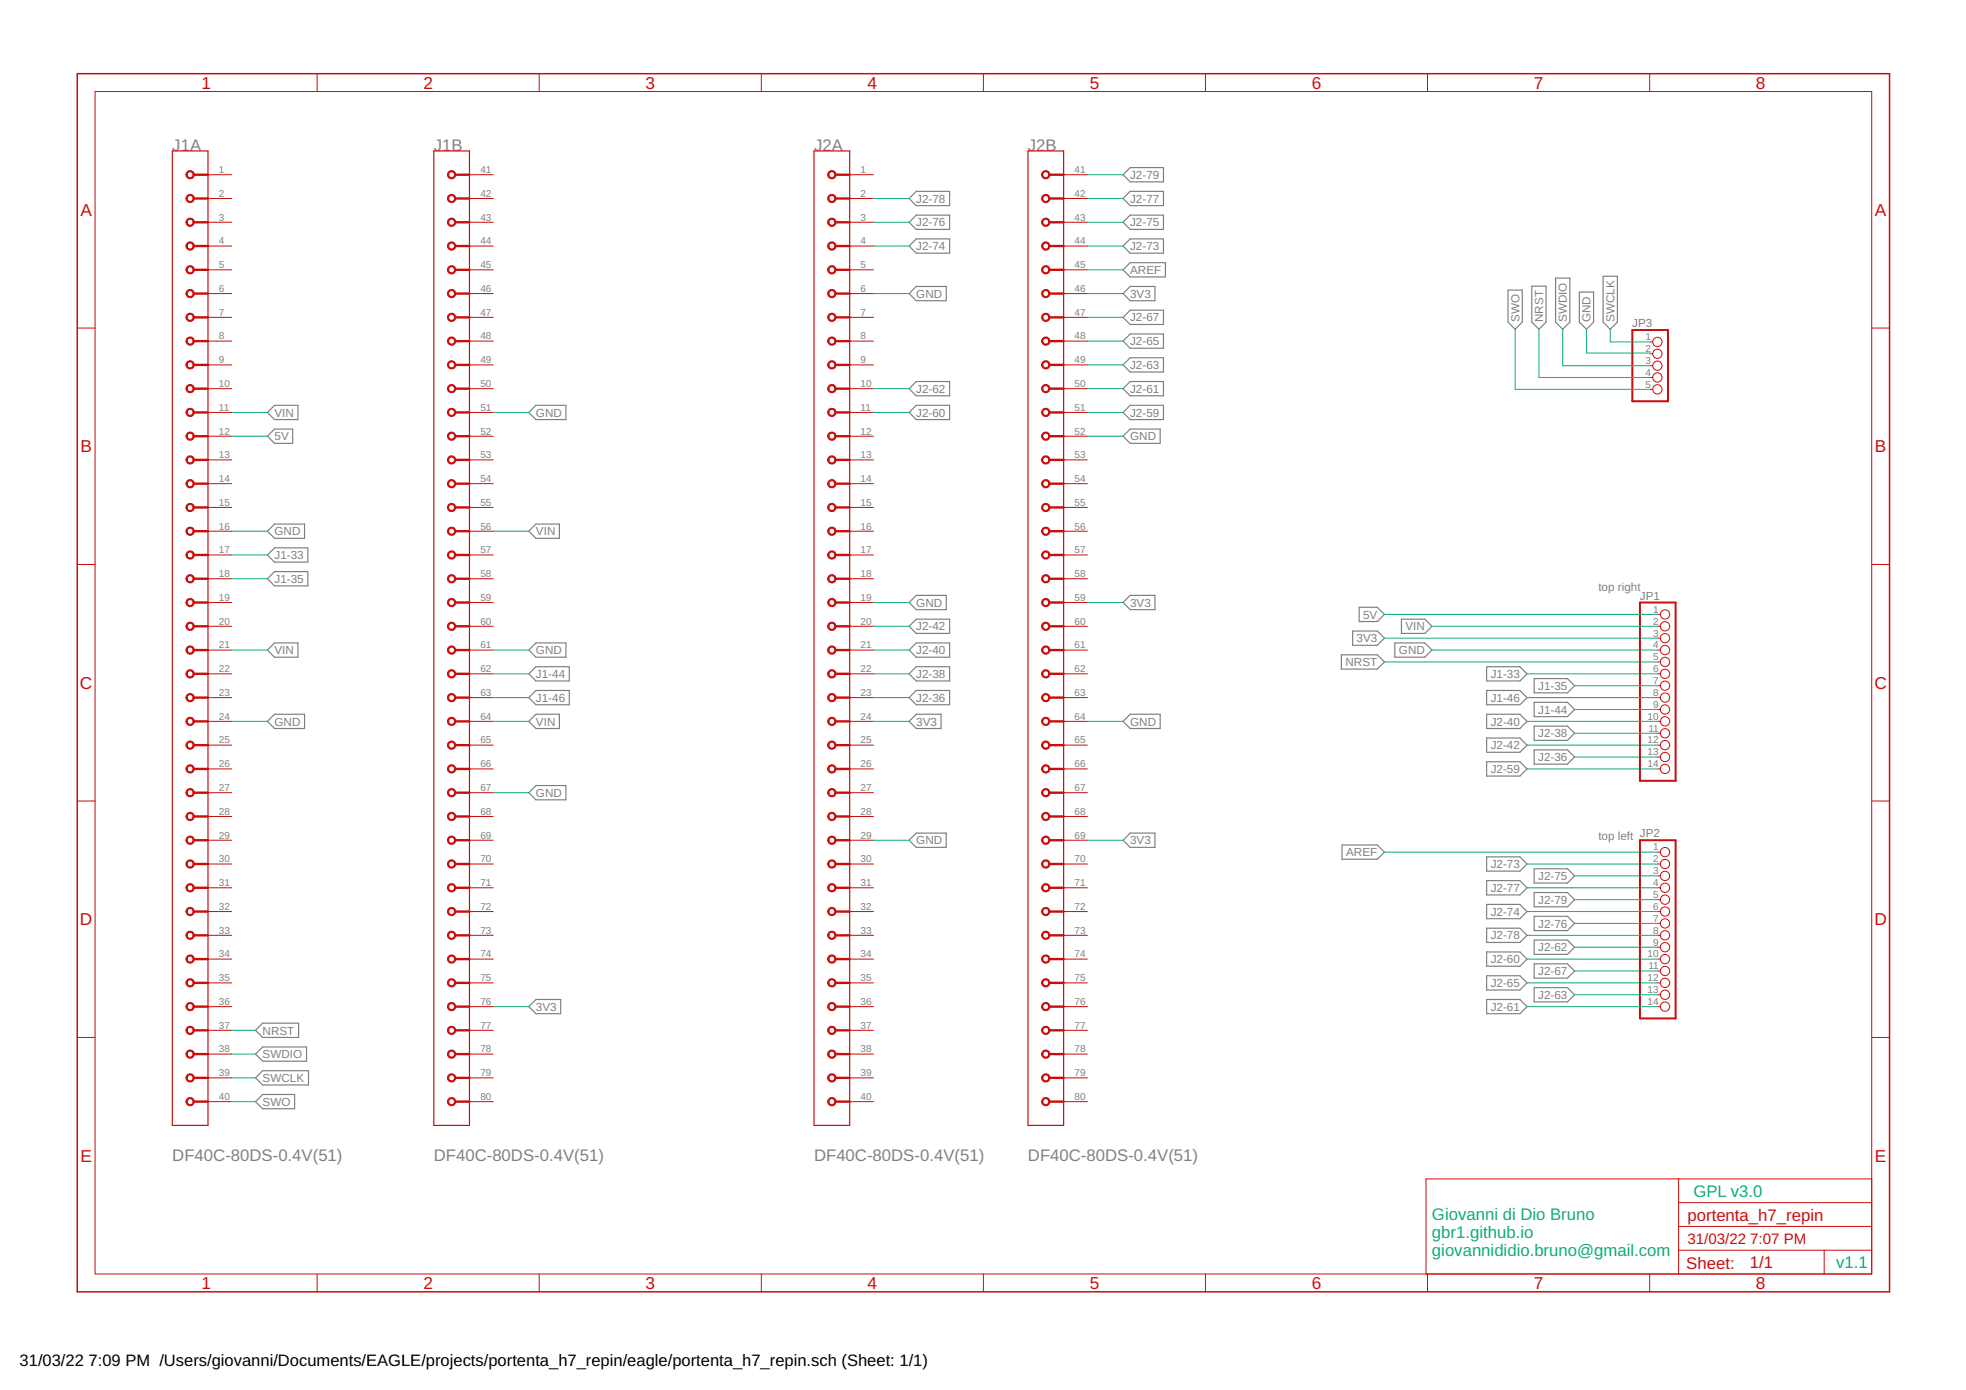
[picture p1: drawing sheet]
<svg xmlns="http://www.w3.org/2000/svg" width="420mm" height="297mm" viewBox="0 0 420 297" stroke-linecap="round" stroke-linejoin="round" font-family="sans-serif">
<defs><g id="words">
<g font-size="3.7" fill="#c90d0c">
<text x="43" y="18.9">1</text>
<text x="90.5" y="18.9">2</text>
<text x="138" y="18.9">3</text>
<text x="185.4" y="18.9">4</text>
<text x="232.9" y="18.9">5</text>
<text x="280.3" y="18.9">6</text>
<text x="327.8" y="18.9">7</text>
<text x="375.3" y="18.9">8</text>
<text x="17.2" y="46.1">A</text>
<text x="400.7" y="46.1">A</text>
<text x="17.2" y="96.7">B</text>
<text x="400.7" y="96.7">B</text>
<text x="17.1" y="147.2">C</text>
<text x="400.6" y="147.2">C</text>
<text x="17.1" y="197.7">D</text>
<text x="400.6" y="197.7">D</text>
<text x="17.2" y="248.3">E</text>
<text x="400.7" y="248.3">E</text>
<text x="43" y="275.4">1</text>
<text x="90.5" y="275.4">2</text>
<text x="138" y="275.4">3</text>
<text x="185.4" y="275.4">4</text>
<text x="232.9" y="275.4">5</text>
<text x="280.3" y="275.4">6</text>
<text x="327.8" y="275.4">7</text>
<text x="375.3" y="275.4">8</text>
</g>
<g font-size="3.6" fill="#808080">
<text x="36.8" y="32.3">J1A</text>
<text x="92.7" y="32.3">J1B</text>
<text x="174" y="32.3">J2A</text>
<text x="219.7" y="32.3">J2B</text>
<text x="36.8" y="248.1">DF40C-80DS-0.4V(51)</text>
<text x="92.7" y="248.1">DF40C-80DS-0.4V(51)</text>
<text x="174" y="248.1">DF40C-80DS-0.4V(51)</text>
<text x="219.7" y="248.1">DF40C-80DS-0.4V(51)</text>
</g>
<g font-size="3.6" fill="#0dab76">
<text x="361.9" y="255.7">GPL v3.0</text>
<text x="306" y="260.8">Giovanni di Dio Bruno</text>
<text x="306" y="264.6">gbr1.github.io</text>
<text x="306" y="268.4">giovannididio.bruno@gmail.com</text>
<text x="392.4" y="271">v1.1</text>
</g>
<g font-size="3.6" fill="#c90d0c">
<text x="360.6" y="260.8">portenta_h7_repin</text>
<text x="360.4" y="271.1">Sheet:</text>
<text x="374" y="271">1/1</text>
</g>
<g font-size="3.5">
<text x="4.2" y="291.8">31/03/22</text>
<text x="18.9" y="291.8">7:09 PM /Users/giovanni/Documents/EAGLE/projects/portenta_h7_repin/eagle/portenta_h7_repin.sch (Sheet: 1/1)</text>
</g>
<g font-size="3.2" fill="#c90d0c">
<text x="360.6" y="265.9">31/03/22</text>
<text x="374.1" y="265.9">7:07 PM</text>
</g>
<g font-size="2.5" fill="#808080">
<text x="241.5" y="38.2">J2-79</text>
<text x="195.8" y="43.3">J2-78</text>
<text x="241.5" y="43.3">J2-77</text>
<text x="195.8" y="53.5">J2-74</text>
<text x="195.8" y="48.4">J2-76</text>
<text x="241.5" y="53.5">J2-73</text>
<text x="241.5" y="48.4">J2-75</text>
<text x="241.5" y="58.5">AREF</text>
<text x="195.8" y="63.6">GND</text>
<text x="241.5" y="63.6">3V3</text>
<text x="241.5" y="68.7">J2-67</text>
<text x="324.7" y="68.8" transform="rotate(-90 324.7 68.8)">SWO</text>
<text x="329.8" y="68.8" transform="rotate(-90 329.8 68.8)">NRST</text>
<text x="334.9" y="68.8" transform="rotate(-90 334.9 68.8)">SWDIO</text>
<text x="339.9" y="68.8" transform="rotate(-90 339.9 68.8)">GND</text>
<text x="345" y="68.8" transform="rotate(-90 345 68.8)">SWCLK</text>
<text x="348.8" y="69.9">JP3</text>
<text x="241.5" y="73.8">J2-65</text>
<text x="195.8" y="83.9">J2-62</text>
<text x="241.5" y="78.9">J2-63</text>
<text x="241.5" y="83.9">J2-61</text>
<text x="58.7" y="89">VIN</text>
<text x="114.5" y="89">GND</text>
<text x="195.8" y="89">J2-60</text>
<text x="241.5" y="89">J2-59</text>
<text x="58.7" y="94.1">5V</text>
<text x="241.5" y="94.1">GND</text>
<text x="58.7" y="114.4">GND</text>
<text x="58.7" y="119.5">J1-33</text>
<text x="114.5" y="114.4">VIN</text>
<text x="58.7" y="124.6">J1-35</text>
<text x="195.8" y="129.7">GND</text>
<text x="241.5" y="129.7">3V3</text>
<text x="341.6" y="126.2">top right</text>
<text x="350.5" y="128.1">JP1</text>
<text x="195.8" y="134.7">J2-42</text>
<text x="289.9" y="137.3">3V3</text>
<text x="291.3" y="132.2">5V</text>
<text x="300.3" y="134.7">VIN</text>
<text x="58.7" y="139.8">VIN</text>
<text x="114.5" y="139.8">GND</text>
<text x="195.8" y="139.8">J2-40</text>
<text x="287.6" y="142.3">NRST</text>
<text x="299" y="139.8">GND</text>
<text x="114.5" y="150">J1-46</text>
<text x="114.5" y="144.9">J1-44</text>
<text x="195.8" y="144.9">J2-38</text>
<text x="195.8" y="150">J2-36</text>
<text x="318.6" y="144.9">J1-33</text>
<text x="318.6" y="150">J1-46</text>
<text x="328.7" y="147.4">J1-35</text>
<text x="58.7" y="155">GND</text>
<text x="114.5" y="155">VIN</text>
<text x="195.8" y="155">3V3</text>
<text x="241.5" y="155">GND</text>
<text x="318.6" y="155">J2-40</text>
<text x="328.7" y="152.5">J1-44</text>
<text x="318.6" y="160.1">J2-42</text>
<text x="328.7" y="157.6">J2-38</text>
<text x="318.6" y="165.2">J2-59</text>
<text x="328.7" y="162.7">J2-36</text>
<text x="114.5" y="170.3">GND</text>
<text x="341.6" y="179.6">top left</text>
<text x="350.5" y="178.9">JP2</text>
<text x="195.8" y="180.4">GND</text>
<text x="241.5" y="180.4">3V3</text>
<text x="287.7" y="183">AREF</text>
<text x="318.6" y="185.5">J2-73</text>
<text x="318.6" y="190.6">J2-77</text>
<text x="328.7" y="188.1">J2-75</text>
<text x="318.6" y="195.7">J2-74</text>
<text x="328.7" y="193.1">J2-79</text>
<text x="318.6" y="200.8">J2-78</text>
<text x="328.7" y="198.2">J2-76</text>
<text x="328.7" y="203.3">J2-62</text>
<text x="318.6" y="205.8">J2-60</text>
<text x="328.7" y="208.4">J2-67</text>
<text x="114.5" y="216">3V3</text>
<text x="318.6" y="210.9">J2-65</text>
<text x="318.6" y="216">J2-61</text>
<text x="328.7" y="213.5">J2-63</text>
<text x="56.1" y="221.1">NRST</text>
<text x="56.1" y="226.2">SWDIO</text>
<text x="56.1" y="231.2">SWCLK</text>
<text x="56.1" y="236.3">SWO</text>
</g>
<g font-size="2.1" fill="#808080">
<text x="46.8" y="37">1</text>
<text x="102.7" y="37">41</text>
<text x="183.9" y="37">1</text>
<text x="229.6" y="37">41</text>
<text x="46.8" y="42.1">2</text>
<text x="46.8" y="47.1">3</text>
<text x="102.7" y="42.1">42</text>
<text x="102.7" y="47.1">43</text>
<text x="183.9" y="42.1">2</text>
<text x="183.9" y="47.1">3</text>
<text x="229.6" y="42.1">42</text>
<text x="229.6" y="47.1">43</text>
<text x="46.8" y="52.2">4</text>
<text x="102.7" y="52.2">44</text>
<text x="183.9" y="52.2">4</text>
<text x="229.6" y="52.2">44</text>
<text x="46.8" y="57.3">5</text>
<text x="102.7" y="57.3">45</text>
<text x="183.9" y="57.3">5</text>
<text x="229.6" y="57.3">45</text>
<text x="46.8" y="62.4">6</text>
<text x="102.7" y="62.4">46</text>
<text x="183.9" y="62.4">6</text>
<text x="229.6" y="62.4">46</text>
<text x="46.8" y="67.5">7</text>
<text x="102.7" y="67.5">47</text>
<text x="183.9" y="67.5">7</text>
<text x="229.6" y="67.5">47</text>
<text x="46.8" y="72.5">8</text>
<text x="46.8" y="77.6">9</text>
<text x="102.7" y="72.5">48</text>
<text x="102.7" y="77.6">49</text>
<text x="183.9" y="72.5">8</text>
<text x="183.9" y="77.6">9</text>
<text x="229.6" y="72.5">48</text>
<text x="229.6" y="77.6">49</text>
<text x="351.7" y="72.7">1</text>
<text x="351.7" y="75.2">2</text>
<text x="351.7" y="77.8">3</text>
<text x="46.8" y="82.7">10</text>
<text x="102.7" y="82.7">50</text>
<text x="183.9" y="82.7">10</text>
<text x="229.6" y="82.7">50</text>
<text x="351.7" y="80.3">4</text>
<text x="351.7" y="82.9">5</text>
<text x="46.8" y="87.8">11</text>
<text x="102.7" y="87.8">51</text>
<text x="183.9" y="87.8">11</text>
<text x="229.6" y="87.8">51</text>
<text x="46.8" y="92.9">12</text>
<text x="102.7" y="92.9">52</text>
<text x="183.9" y="92.9">12</text>
<text x="229.6" y="92.9">52</text>
<text x="46.8" y="97.9">13</text>
<text x="102.7" y="97.9">53</text>
<text x="183.9" y="97.9">13</text>
<text x="229.6" y="97.9">53</text>
<text x="46.8" y="103">14</text>
<text x="102.7" y="103">54</text>
<text x="183.9" y="103">14</text>
<text x="229.6" y="103">54</text>
<text x="46.8" y="108.1">15</text>
<text x="46.8" y="113.2">16</text>
<text x="102.7" y="108.1">55</text>
<text x="102.7" y="113.2">56</text>
<text x="183.9" y="108.1">15</text>
<text x="183.9" y="113.2">16</text>
<text x="229.6" y="108.1">55</text>
<text x="229.6" y="113.2">56</text>
<text x="46.8" y="118.2">17</text>
<text x="102.7" y="118.2">57</text>
<text x="183.9" y="118.2">17</text>
<text x="229.6" y="118.2">57</text>
<text x="46.8" y="123.3">18</text>
<text x="102.7" y="123.3">58</text>
<text x="183.9" y="123.3">18</text>
<text x="229.6" y="123.3">58</text>
<text x="46.8" y="128.4">19</text>
<text x="102.7" y="128.4">59</text>
<text x="183.9" y="128.4">19</text>
<text x="229.6" y="128.4">59</text>
<text x="353.3" y="130.9">1</text>
<text x="46.8" y="133.5">20</text>
<text x="102.7" y="133.5">60</text>
<text x="183.9" y="133.5">20</text>
<text x="229.6" y="133.5">60</text>
<text x="353.3" y="133.5">2</text>
<text x="353.3" y="136">3</text>
<text x="46.8" y="138.6">21</text>
<text x="46.8" y="143.6">22</text>
<text x="102.7" y="138.6">61</text>
<text x="102.7" y="143.6">62</text>
<text x="183.9" y="138.6">21</text>
<text x="183.9" y="143.6">22</text>
<text x="229.6" y="138.6">61</text>
<text x="229.6" y="143.6">62</text>
<text x="353.3" y="138.6">4</text>
<text x="353.3" y="141.1">5</text>
<text x="353.3" y="143.6">6</text>
<text x="46.8" y="148.7">23</text>
<text x="102.7" y="148.7">63</text>
<text x="183.9" y="148.7">23</text>
<text x="229.6" y="148.7">63</text>
<text x="353.3" y="146.2">7</text>
<text x="353.3" y="148.7">8</text>
<text x="46.8" y="153.8">24</text>
<text x="102.7" y="153.8">64</text>
<text x="183.9" y="153.8">24</text>
<text x="229.6" y="153.8">64</text>
<text x="352.1" y="153.8">10</text>
<text x="353.3" y="151.3">9</text>
<text x="46.8" y="158.9">25</text>
<text x="102.7" y="158.9">65</text>
<text x="183.9" y="158.9">25</text>
<text x="229.6" y="158.9">65</text>
<text x="352.1" y="158.9">12</text>
<text x="352.1" y="161.4">13</text>
<text x="352.3" y="156.3">11</text>
<text x="46.8" y="164">26</text>
<text x="102.7" y="164">66</text>
<text x="183.9" y="164">26</text>
<text x="229.6" y="164">66</text>
<text x="352.1" y="164">14</text>
<text x="46.8" y="169">27</text>
<text x="102.7" y="169">67</text>
<text x="183.9" y="169">27</text>
<text x="229.6" y="169">67</text>
<text x="46.8" y="174.1">28</text>
<text x="46.8" y="179.2">29</text>
<text x="102.7" y="174.1">68</text>
<text x="102.7" y="179.2">69</text>
<text x="183.9" y="174.1">28</text>
<text x="183.9" y="179.2">29</text>
<text x="229.6" y="174.1">68</text>
<text x="229.6" y="179.2">69</text>
<text x="46.8" y="184.3">30</text>
<text x="102.7" y="184.3">70</text>
<text x="183.9" y="184.3">30</text>
<text x="229.6" y="184.3">70</text>
<text x="353.3" y="181.7">1</text>
<text x="353.3" y="184.3">2</text>
<text x="46.8" y="189.4">31</text>
<text x="102.7" y="189.4">71</text>
<text x="183.9" y="189.4">31</text>
<text x="229.6" y="189.4">71</text>
<text x="353.3" y="186.8">3</text>
<text x="353.3" y="189.4">4</text>
<text x="353.3" y="191.9">5</text>
<text x="46.8" y="194.4">32</text>
<text x="102.7" y="194.4">72</text>
<text x="183.9" y="194.4">32</text>
<text x="229.6" y="194.4">72</text>
<text x="353.3" y="194.4">6</text>
<text x="353.3" y="197">7</text>
<text x="46.8" y="199.5">33</text>
<text x="102.7" y="199.5">73</text>
<text x="183.9" y="199.5">33</text>
<text x="229.6" y="199.5">73</text>
<text x="353.3" y="199.5">8</text>
<text x="353.3" y="202.1">9</text>
<text x="46.8" y="204.6">34</text>
<text x="46.8" y="209.7">35</text>
<text x="102.7" y="204.6">74</text>
<text x="102.7" y="209.7">75</text>
<text x="183.9" y="204.6">34</text>
<text x="183.9" y="209.7">35</text>
<text x="229.6" y="204.6">74</text>
<text x="229.6" y="209.7">75</text>
<text x="352.1" y="204.6">10</text>
<text x="352.1" y="209.7">12</text>
<text x="352.3" y="207.1">11</text>
<text x="46.8" y="214.8">36</text>
<text x="102.7" y="214.8">76</text>
<text x="183.9" y="214.8">36</text>
<text x="229.6" y="214.8">76</text>
<text x="352.1" y="212.2">13</text>
<text x="352.1" y="214.8">14</text>
<text x="46.8" y="219.8">37</text>
<text x="102.7" y="219.8">77</text>
<text x="183.9" y="219.8">37</text>
<text x="229.6" y="219.8">77</text>
<text x="46.8" y="224.9">38</text>
<text x="102.7" y="224.9">78</text>
<text x="183.9" y="224.9">38</text>
<text x="229.6" y="224.9">78</text>
<text x="46.8" y="230">39</text>
<text x="102.7" y="230">79</text>
<text x="183.9" y="230">39</text>
<text x="229.6" y="230">79</text>
<text x="46.8" y="235.1">40</text>
<text x="102.7" y="235.1">80</text>
<text x="183.9" y="235.1">40</text>
<text x="229.6" y="235.1">80</text>
</g>
</g></defs>
<g fill="none" stroke="#808080" stroke-width=".25">
<path d="M240 37.3l1.5-1.5h7.1v3.1h-7.1zM195.8 51.1h7.1v3h-7.1l-1.5-1.5zM195.8 46h7.1v3h-7.1l-1.5-1.5zM195.8 40.9h7.1v3h-7.1l-1.5-1.5zM240 57.7l1.5-1.6h7.6v3.1h-7.6zM240 52.6l1.5-1.5h7.1v3h-7.1zM240 42.4l1.5-1.5h7.1v3h-7.1zM240 47.5l1.5-1.5h7.1v3h-7.1zM332.4 59.4h3.1v9.4l-1.5 1.6-1.6-1.6zM342.6 59h3.1v9.8l-1.6 1.6-1.5-1.6zM195.8 61.2h6.4v3.1h-6.4l-1.5-1.6zM240 67.8l1.5-1.5h7.1v3h-7.1z"/>
<path d="M240 72.9l1.5-1.5h7.1v3h-7.1zM240 78l1.5-1.5h7.1v3h-7.1zM240 62.7l1.5-1.5h5.3v3.1h-5.3zM322.3 62h3v6.8l-1.5 1.6-1.5-1.6zM327.4 61.2h3v7.6l-1.5 1.6-1.5-1.6zM337.5 62.4h3.1v6.4l-1.6 1.6-1.5-1.6zM57.1 93.2l1.6-1.5h3.8v3h-3.8zM58.7 86.6h5v3.1h-5l-1.6-1.6zM113 88.1l1.5-1.5h6.4v3.1h-6.4zM194.3 88.1l1.5-1.5h7.1v3.1h-7.1zM194.3 83.1l1.5-1.6h7.1v3.1h-7.1zM240 83.1l1.5-1.6h7.1v3.1h-7.1z"/>
<path d="M240 88.1l1.5-1.5h7.1v3.1h-7.1zM241.5 91.7h6.4v3h-6.4l-1.5-1.5zM57.1 118.6l1.6-1.5h7.1v3h-7.1zM58.7 112h6.4v3h-6.4l-1.6-1.5zM113 113.5l1.5-1.5h5v3h-5zM57.1 123.7l1.6-1.5h7.1v3h-7.1zM58.7 137.4h5v3h-5l-1.6-1.5zM114.5 137.4h6.4v3h-6.4l-1.5-1.5zM195.8 132.3h7.1v3.1h-7.1l-1.5-1.6zM195.8 137.4h7.1v3h-7.1l-1.5-1.5zM195.8 127.2h6.4v3.1h-6.4l-1.5-1.5zM240 128.8l1.5-1.6h5.3v3.1h-5.3z"/>
<path d="M286.7 139.9h7.6l1.6 1.6-1.6 1.5h-7.6zM289.1 134.9h5.2l1.6 1.5-1.6 1.5h-5.2zM290.5 129.8h3.8l1.6 1.5-1.6 1.5h-3.8zM298.1 137.4h6.4l1.5 1.5-1.5 1.5h-6.4zM299.5 132.3h5l1.5 1.5-1.5 1.6h-5zM58.7 152.6h6.4v3.1h-6.4l-1.6-1.5zM113 154.2l1.5-1.6h5v3.1h-5zM113 144l1.5-1.5h7.2v3h-7.2zM113 149.1l1.5-1.5h7.2v3h-7.2zM195.8 142.5h7.1v3h-7.1l-1.5-1.5zM195.8 147.6h7.1v3h-7.1l-1.5-1.5zM195.8 152.6h5.3v3.1h-5.3l-1.5-1.5z"/>
<path d="M241.5 152.6h6.4v3.1h-6.4l-1.5-1.5zM317.7 142.5h7.1l1.5 1.5-1.5 1.5h-7.1zM317.7 147.6h7.1l1.5 1.5-1.5 1.5h-7.1zM317.7 152.6h7.1l1.5 1.6-1.5 1.5h-7.1zM317.7 157.7h7.1l1.5 1.5-1.5 1.6h-7.1zM327.9 145h7.1l1.5 1.5-1.5 1.6h-7.1zM327.9 150.1h7.1l1.5 1.5-1.5 1.5h-7.1zM327.9 155.2h7.1l1.5 1.5-1.5 1.5h-7.1zM113 169.4l1.5-1.5h6.4v3h-6.4zM195.8 178h6.4v3.1h-6.4l-1.5-1.5zM240 179.6l1.5-1.6h5.3v3.1h-5.3zM317.7 162.8h7.1l1.5 1.5-1.5 1.5h-7.1z"/>
<path d="M327.9 160.3h7.1l1.5 1.5-1.5 1.5h-7.1zM286.8 180.6h7.5l1.6 1.5-1.6 1.5h-7.5zM317.7 183.1h7.1l1.5 1.5-1.5 1.6h-7.1zM317.7 188.2h7.1l1.5 1.5-1.5 1.5h-7.1zM317.7 193.3h7.1l1.5 1.5-1.5 1.5h-7.1zM317.7 198.4h7.1l1.5 1.5-1.5 1.5h-7.1zM327.9 185.7h7.1l1.5 1.5-1.5 1.5h-7.1zM327.9 190.7h7.1l1.5 1.6-1.5 1.5h-7.1zM327.9 195.8h7.1l1.5 1.5-1.5 1.6h-7.1zM56.1 218.7h7.7v3h-7.7l-1.5-1.5zM113 215.1l1.5-1.5h5.3v3h-5.3zM317.7 203.4h7.1l1.5 1.6-1.5 1.5h-7.1z"/>
<path d="M317.7 208.5h7.1l1.5 1.5-1.5 1.6h-7.1zM317.7 213.6h7.1l1.5 1.5-1.5 1.5h-7.1zM327.9 200.9h7.1l1.5 1.5-1.5 1.5h-7.1zM327.9 206h7.1l1.5 1.5-1.5 1.5h-7.1zM327.9 211.1h7.1l1.5 1.5-1.5 1.5h-7.1zM56.1 228.8h9.8v3.1h-9.8l-1.5-1.6zM56.1 223.7h9.4v3.1h-9.4l-1.5-1.5zM56.1 233.9h6.9v3h-6.9l-1.5-1.5z"/>
</g>
<path d="M36.8 32.3h7.6v208.2h-7.6zM92.7 32.3h7.6v208.2h-7.6zM174 32.3h7.6v208.2h-7.6zM219.7 32.3h7.6v208.2h-7.6z" fill="none" stroke="#c90d0c" stroke-width=".25"/>
<g fill="none" stroke="#c90d0c" stroke-width=".51">
<path d="M41.4 37.3h3M97.3 37.3h3M178.5 37.3h3.1M224.3 37.3h3M41.4 42.4h3M41.4 47.5h3M41.4 52.6h3M41.4 57.7h3M97.3 42.4h3M97.3 47.5h3M97.3 52.6h3M97.3 57.7h3"/>
<path d="M178.5 42.4h3.1M178.5 47.5h3.1M178.5 52.6h3.1M178.5 57.7h3.1M224.3 42.4h3M224.3 47.5h3M224.3 52.6h3M224.3 57.7h3M41.4 62.7h3M41.4 67.8h3M41.4 72.9h3M41.4 78h3"/>
<path d="M97.3 62.7h3M97.3 67.8h3M97.3 72.9h3M97.3 78h3M178.5 62.7h3.1M178.5 67.8h3.1M178.5 72.9h3.1M178.5 78h3.1M224.3 62.7h3M224.3 67.8h3M224.3 72.9h3M224.3 78h3"/>
<path d="M41.4 83.1h3M41.4 88.1h3M41.4 93.2h3M41.4 98.3h3M97.3 83.1h3M97.3 88.1h3M97.3 93.2h3M97.3 98.3h3M178.5 83.1h3.1M178.5 88.1h3.1M178.5 93.2h3.1M178.5 98.3h3.1"/>
<path d="M224.3 83.1h3M224.3 88.1h3M224.3 93.2h3M224.3 98.3h3M41.4 103.4h3M41.4 108.4h3M41.4 113.5h3M41.4 118.6h3M97.3 103.4h3M97.3 108.4h3M97.3 113.5h3M97.3 118.6h3"/>
<path d="M178.5 103.4h3.1M178.5 108.4h3.1M178.5 113.5h3.1M178.5 118.6h3.1M224.3 103.4h3M224.3 108.4h3M224.3 113.5h3M224.3 118.6h3M41.4 123.7h3M41.4 128.8h3M41.4 133.8h3M41.4 138.9h3"/>
<path d="M97.3 123.7h3M97.3 128.8h3M97.3 133.8h3M97.3 138.9h3M178.5 123.7h3.1M178.5 128.8h3.1M178.5 133.8h3.1M178.5 138.9h3.1M224.3 123.7h3M224.3 128.8h3M224.3 133.8h3M224.3 138.9h3"/>
<path d="M41.4 144h3M41.4 149.1h3M41.4 154.2h3M41.4 159.2h3M97.3 144h3M97.3 149.1h3M97.3 154.2h3M97.3 159.2h3M178.5 144h3.1M178.5 149.1h3.1M178.5 154.2h3.1M178.5 159.2h3.1"/>
<path d="M224.3 144h3M224.3 149.1h3M224.3 154.2h3M224.3 159.2h3M41.4 164.3h3M41.4 169.4h3M41.4 174.5h3M41.4 179.6h3M97.3 164.3h3M97.3 169.4h3M97.3 174.5h3M97.3 179.6h3"/>
<path d="M178.5 164.3h3.1M178.5 169.4h3.1M178.5 174.5h3.1M178.5 179.6h3.1M224.3 164.3h3M224.3 169.4h3M224.3 174.5h3M224.3 179.6h3M41.4 184.6h3M41.4 189.7h3M41.4 194.8h3M41.4 199.9h3"/>
<path d="M97.3 184.6h3M97.3 189.7h3M97.3 194.8h3M97.3 199.9h3M178.5 184.6h3.1M178.5 189.7h3.1M178.5 194.8h3.1M178.5 199.9h3.1M224.3 184.6h3M224.3 189.7h3M224.3 194.8h3M224.3 199.9h3"/>
<path d="M41.4 205h3M41.4 210h3M41.4 215.1h3M97.3 205h3M97.3 210h3M97.3 215.1h3M178.5 205h3.1M178.5 210h3.1M178.5 215.1h3.1M224.3 205h3M224.3 210h3M224.3 215.1h3"/>
<path d="M41.4 220.2h3M41.4 225.3h3M41.4 230.3h3M41.4 235.4h3M97.3 220.2h3M97.3 225.3h3M97.3 230.3h3M97.3 235.4h3M178.5 220.2h3.1M178.5 225.3h3.1M178.5 230.3h3.1M178.5 235.4h3.1"/>
<path d="M224.3 220.2h3M224.3 225.3h3M224.3 230.3h3M224.3 235.4h3"/>
</g>
<g fill="none" stroke="#c90d0c" stroke-width=".21">
<path d="M20.3 19.6h379.7v252.6h-379.7zM67.8 15.7v3.9M115.2 15.7v3.9M162.7 15.7v3.9M210.2 15.7v3.9M257.6 15.7v3.9M305.1 15.7v3.9M352.6 15.7v3.9M44.4 37.3l.1 .1M44.4 37.3h5.1M100.3 37.3h5.1M100.3 37.3l.1 .1"/>
<path d="M181.6 37.3h5.1M181.6 37.3v.1M232.4 37.3l-5.1 .1M44.4 42.4h.1M44.4 47.5h.1M44.4 52.6h.1M44.4 42.4h5.1M44.4 47.5h5.1M44.4 52.6h5.1M49.5 57.7h-5M100.3 42.4h5.1M100.3 47.5h5.1"/>
<path d="M100.3 52.6h5.1M100.3 42.4h.1M100.3 47.5h.1M100.3 52.6h.1M105.4 57.7h-5M181.6 42.4h5.1M181.6 47.5h5.1M181.6 52.6h5.1M181.6 42.4h.1M181.6 47.5h.1M181.6 52.6h.1M186.7 57.7h-5.1"/>
<path d="M232.4 42.4h-5.1M232.4 47.5h-5.1M232.4 52.6h-5.1M232.4 57.7h-5.1M16.5 70.1h3.8M49.5 62.7l-5 .1M49.5 67.8h-5M49.5 72.9h-5M49.5 78h-5M105.4 62.7l-5 .1M105.4 67.8h-5M105.4 72.9h-5"/>
<path d="M105.4 78h-5M186.7 62.7l-5.1 .1M186.7 67.8h-5.1M186.7 72.9h-5.1M186.7 78h-5.1M232.4 62.7l-5.1 .1M232.4 67.8h-5.1M232.4 72.9h-5.1M232.4 78h-5.1M352.7 73.1h.5M352.7 75.6h.5M352.7 78.1h.5"/>
<path d="M400 70.1h3.8M44.4 83.1h.1M44.4 88.1l.1 .1M44.4 93.2h.1M44.4 83.1h5.1M44.4 88.1h5.1M44.4 93.2h5.1M49.5 98.3h-5M100.3 83.1h5.1M100.3 88.1h5.1M100.3 93.2h5.1M100.3 83.1h.1"/>
<path d="M100.3 88.1l.1 .1M100.3 93.2h.1M105.4 98.3h-5M181.6 83.1h5.1M181.6 88.1h5.1M181.6 93.2h5.1M181.6 83.1h.1M181.6 88.1v.1M181.6 93.2h.1M186.7 98.3h-5.1M232.4 83.1h-5.1M232.4 88.1l-5.1 .1"/>
<path d="M232.4 93.2h-5.1M232.4 98.3h-5.1M352.7 80.7h.5M352.7 83.2h.5M44.4 103.4h.1M44.4 108.4l.1 .1M44.4 113.5h.1M44.4 118.6h.1M44.4 103.4h5.1M44.4 108.4h5.1M44.4 113.5h5.1M44.4 118.6h5.1"/>
<path d="M100.3 103.4h5.1M100.3 108.4h5.1M100.3 113.5h5.1M100.3 118.6h5.1M100.3 103.4h.1M100.3 108.4l.1 .1M100.3 113.5h.1M100.3 118.6h.1M181.6 103.4h5.1M181.6 108.4h5.1M181.6 113.5h5.1M181.6 118.6h5.1"/>
<path d="M181.6 103.4h.1M181.6 108.4v.1M181.6 113.5h.1M181.6 118.6h.1M232.4 103.4h-5.1M232.4 108.4l-5.1 .1M232.4 113.5h-5.1M232.4 118.6h-5.1M16.5 120.6h3.8M44.4 123.7h.1M44.4 128.8h.1M44.4 133.8l.1 .1"/>
<path d="M44.4 138.9h.1M44.4 123.7h5.1M44.4 128.8h5.1M44.4 133.8h5.1M44.4 138.9h5.1M100.3 123.7h5.1M100.3 128.8h5.1M100.3 133.8h5.1M100.3 138.9h5.1M100.3 123.7h.1M100.3 128.8h.1M100.3 133.8l.1 .1"/>
<path d="M100.3 138.9h.1M181.6 123.7h5.1M181.6 128.8h5.1M181.6 133.8h5.1M181.6 138.9h5.1M181.6 123.7h.1M181.6 128.8h.1M181.6 133.8v.1M181.6 138.9h.1M232.4 123.7h-5.1M232.4 128.8h-5.1M232.4 133.8l-5.1 .1"/>
<path d="M232.4 138.9h-5.1M354.3 133.8h.6M354.3 138.9h.6M354.3 131.3h.6M354.3 136.4h.6M400 120.6h3.8M49.5 144h-5M49.5 149.1h-5M49.5 154.2h-5M49.5 159.2l-5 .1M105.4 144h-5M105.4 149.1h-5"/>
<path d="M105.4 154.2h-5M105.4 159.2l-5 .1M186.7 144h-5.1M186.7 149.1h-5.1M186.7 154.2h-5.1M186.7 159.2l-5.1 .1M232.4 144h-5.1M232.4 149.1h-5.1M232.4 154.2h-5.1M232.4 159.2l-5.1 .1M354.3 144h.6M354.3 149.1h.6"/>
<path d="M354.3 154.2h.6M354.3 159.2h.6M354.3 141.5h.6M354.3 146.5h.6M354.3 151.6h.6M354.3 156.7h.6M16.5 171.2h3.8M44.4 169.4h.1M44.4 174.5h.1M44.4 179.6h.1M44.4 169.4h5.1M44.4 174.5h5.1"/>
<path d="M44.4 179.6h5.1M49.5 164.3h-5M100.3 169.4h5.1M100.3 174.5h5.1M100.3 179.6h5.1M100.3 169.4h.1M100.3 174.5h.1M100.3 179.6h.1M105.4 164.3h-5M181.6 169.4h5.1M181.6 174.5h5.1M181.6 179.6h5.1"/>
<path d="M181.6 169.4h.1M181.6 174.5h.1M181.6 179.6h.1M186.7 164.3h-5.1M232.4 164.3h-5.1M232.4 169.4h-5.1M232.4 174.5h-5.1M232.4 179.6h-5.1M354.3 164.3h.6M354.3 161.8h.6M400 171.2h3.8M44.4 184.6l.1 .1"/>
<path d="M44.4 189.7h.1M44.4 194.8h.1M44.4 199.9h.1M44.4 184.6h5.1M44.4 189.7h5.1M44.4 194.8h5.1M44.4 199.9h5.1M100.3 184.6h5.1M100.3 189.7h5.1M100.3 194.8h5.1M100.3 199.9h5.1M100.3 184.6l.1 .1"/>
<path d="M100.3 189.7h.1M100.3 194.8h.1M100.3 199.9h.1M181.6 184.6h5.1M181.6 189.7h5.1M181.6 194.8h5.1M181.6 199.9h5.1M181.6 184.6v.1M181.6 189.7h.1M181.6 194.8h.1M181.6 199.9h.1M232.4 184.6l-5.1 .1"/>
<path d="M232.4 189.7h-5.1M232.4 194.8h-5.1M232.4 199.9h-5.1M354.3 184.6h.6M354.3 189.7h.6M354.3 194.8h.6M354.3 199.9h.6M354.3 182.1h.6M354.3 187.2h.6M354.3 192.3h.6M354.3 197.3h.6M49.5 205h-5"/>
<path d="M49.5 210l-5 .1M49.5 215.1h-5M105.4 205h-5M105.4 210l-5 .1M105.4 215.1h-5M186.7 205h-5.1M186.7 210l-5.1 .1M186.7 215.1h-5.1M232.4 205h-5.1M232.4 210l-5.1 .1M232.4 215.1h-5.1M354.3 205h.6"/>
<path d="M354.3 210h.6M354.3 215.1h.6M354.3 202.4h.6M354.3 207.5h.6M354.3 212.6h.6M16.5 221.7h3.8M44.4 220.2h.1M44.4 225.3h.1M44.4 220.2h5.1M44.4 225.3h5.1M49.5 230.3l-5 .1M49.5 235.4h-5"/>
<path d="M100.3 220.2h5.1M100.3 225.3h5.1M100.3 220.2h.1M100.3 225.3h.1M105.4 230.3l-5 .1M105.4 235.4h-5M181.6 220.2h5.1M181.6 225.3h5.1M181.6 220.2h.1M181.6 225.3h.1M186.7 230.3l-5.1 .1M186.7 235.4h-5.1"/>
<path d="M232.4 220.2h-5.1M232.4 225.3h-5.1M232.4 230.3l-5.1 .1M232.4 235.4h-5.1M400 221.7h3.8M358.7 251.9v20.3M358.7 257h41.3M400 251.9h-95.2v20.3M67.8 272.2v3.9M115.2 272.2v3.9M162.7 272.2v3.9M210.2 272.2v3.9"/>
<path d="M257.6 272.2v3.9M305.1 272.2v3.9M352.6 272.2v3.9M358.7 267.2h41.3M358.7 262.1h41.3M389.8 267.2v5"/>
<circle cx="354.2" cy="73.1" r=".99"/>
<circle cx="354.2" cy="78.1" r=".99"/>
<circle cx="354.2" cy="75.6" r=".99"/>
<circle cx="354.2" cy="80.7" r=".99"/>
<circle cx="354.2" cy="83.2" r=".99"/>
<circle cx="355.8" cy="131.3" r=".99"/>
<circle cx="355.8" cy="133.8" r=".99"/>
<circle cx="355.8" cy="138.9" r=".99"/>
<circle cx="355.8" cy="136.4" r=".99"/>
<circle cx="355.8" cy="144" r=".99"/>
<circle cx="355.8" cy="146.5" r=".99"/>
<circle cx="355.8" cy="141.5" r=".99"/>
<circle cx="355.8" cy="149.1" r=".99"/>
<circle cx="355.8" cy="151.6" r=".99"/>
<circle cx="355.8" cy="159.2" r=".99"/>
<circle cx="355.8" cy="154.2" r=".99"/>
<circle cx="355.8" cy="156.7" r=".99"/>
<circle cx="355.8" cy="161.8" r=".99"/>
<circle cx="355.8" cy="164.3" r=".99"/>
<circle cx="355.8" cy="187.2" r=".99"/>
<circle cx="355.8" cy="182.1" r=".99"/>
<circle cx="355.8" cy="184.6" r=".99"/>
<circle cx="355.8" cy="189.7" r=".99"/>
<circle cx="355.8" cy="194.8" r=".99"/>
<circle cx="355.8" cy="197.3" r=".99"/>
<circle cx="355.8" cy="199.9" r=".99"/>
<circle cx="355.8" cy="192.3" r=".99"/>
<circle cx="355.8" cy="205" r=".99"/>
<circle cx="355.8" cy="212.6" r=".99"/>
<circle cx="355.8" cy="202.4" r=".99"/>
<circle cx="355.8" cy="210" r=".99"/>
<circle cx="355.8" cy="207.5" r=".99"/>
<circle cx="355.8" cy="215.1" r=".99"/>
</g>
<g fill="#c90d0c" stroke="#c90d0c" stroke-width=".21">
<path d="M39.9 36.8a.88 .88 0 0 1 1.5 0 .88 .88 0 0 1-.5 1.4 .88 .88 0 0 1-1.1-.9h.2a.63 .63 0 0 1 .9-.5 .63 .63 0 0 1 .1 1.1 .63 .63 0 0 1-1-.4v-.2h-.2z" fill-rule="evenodd"/>
<path d="M39.9 41.9a.88 .88 0 0 1 1.5 0 .88 .88 0 0 1-.5 1.4 .88 .88 0 0 1-1.1-.9h.2a.63 .63 0 0 1 .9-.5 .63 .63 0 0 1 .1 1.1 .63 .63 0 0 1-1-.4v-.2h-.2z" fill-rule="evenodd"/>
<path d="M39.9 46.9a.88 .88 0 0 1 1.5 .1 .88 .88 0 0 1-.5 1.3 .88 .88 0 0 1-1.1-.8h.2a.63 .63 0 0 1 .9-.5 .63 .63 0 0 1 .1 1 .63 .63 0 0 1-1-.3v-.2h-.2z" fill-rule="evenodd"/>
<path d="M39.9 52a.88 .88 0 0 1 1.5 .1 .88 .88 0 0 1-.5 1.3 .88 .88 0 0 1-1.1-.8h.2a.63 .63 0 0 1 .9-.5 .63 .63 0 0 1 .1 1 .63 .63 0 0 1-1-.3v-.2h-.2z" fill-rule="evenodd"/>
<path d="M39.9 57.1a.88 .88 0 0 1 1.5 .1 .88 .88 0 0 1-.5 1.3 .88 .88 0 0 1-1.1-.8h.2a.63 .63 0 0 1 .9-.6 .63 .63 0 0 1 .1 1.1 .63 .63 0 0 1-1-.3v-.2h-.2z" fill-rule="evenodd"/>
<path d="M39.9 62.2a.88 .88 0 0 1 1.5 0 .88 .88 0 0 1-.5 1.4 .88 .88 0 0 1-1.1-.9h.2a.63 .63 0 0 1 .9-.5 .63 .63 0 0 1 .1 1.1 .63 .63 0 0 1-1-.4v-.2h-.2z" fill-rule="evenodd"/>
<path d="M39.9 67.3a.88 .88 0 0 1 1.5 0 .88 .88 0 0 1-.5 1.4 .88 .88 0 0 1-1.1-.9h.2a.63 .63 0 0 1 .9-.5 .63 .63 0 0 1 .1 1 .63 .63 0 0 1-1-.3v-.2h-.2z" fill-rule="evenodd"/>
<path d="M39.9 72.3a.88 .88 0 0 1 1.5 .1 .88 .88 0 0 1-.5 1.3 .88 .88 0 0 1-1.1-.8h.2a.63 .63 0 0 1 .9-.5 .63 .63 0 0 1 .1 1 .63 .63 0 0 1-1-.3v-.2h-.2z" fill-rule="evenodd"/>
<path d="M39.9 77.4a.88 .88 0 0 1 1.5 .1 .88 .88 0 0 1-.5 1.3 .88 .88 0 0 1-1.1-.8h.2a.63 .63 0 0 1 .9-.6 .63 .63 0 0 1 .1 1.1 .63 .63 0 0 1-1-.3v-.2h-.2z" fill-rule="evenodd"/>
<path d="M39.9 82.5a.88 .88 0 0 1 1.5 .1 .88 .88 0 0 1-.5 1.3 .88 .88 0 0 1-1.1-.8h.2a.63 .63 0 0 1 .9-.6 .63 .63 0 0 1 .1 1.1 .63 .63 0 0 1-1-.4v-.1h-.2z" fill-rule="evenodd"/>
<path d="M39.9 87.6a.88 .88 0 0 1 1.5 0 .88 .88 0 0 1-.5 1.4 .88 .88 0 0 1-1.1-.9h.2a.63 .63 0 0 1 .9-.5 .63 .63 0 0 1 .1 1.1 .63 .63 0 0 1-1-.4v-.2h-.2z" fill-rule="evenodd"/>
<path d="M39.9 92.7a.88 .88 0 0 1 1.5 0 .88 .88 0 0 1-.5 1.4 .88 .88 0 0 1-1.1-.9h.2a.63 .63 0 0 1 .9-.5 .63 .63 0 0 1 .1 1 .63 .63 0 0 1-1-.3v-.2h-.2z" fill-rule="evenodd"/>
<path d="M39.9 97.7a.88 .88 0 0 1 1.5 .1 .88 .88 0 0 1-.5 1.3 .88 .88 0 0 1-1.1-.8h.2a.63 .63 0 0 1 .9-.5 .63 .63 0 0 1 .1 1 .63 .63 0 0 1-1-.3v-.2h-.2z" fill-rule="evenodd"/>
<path d="M39.9 102.8a.88 .88 0 0 1 1.5 .1 .88 .88 0 0 1-.5 1.3 .88 .88 0 0 1-1.1-.8h.2a.63 .63 0 0 1 .9-.6 .63 .63 0 0 1 .1 1.1 .63 .63 0 0 1-1-.3v-.2h-.2z" fill-rule="evenodd"/>
<path d="M39.9 107.9a.88 .88 0 0 1 1.5 .1 .88 .88 0 0 1-.5 1.3 .88 .88 0 0 1-1.1-.9h.2a.63 .63 0 0 1 .9-.5 .63 .63 0 0 1 .1 1.1 .63 .63 0 0 1-1-.4v-.2h-.2z" fill-rule="evenodd"/>
<path d="M39.9 113a.88 .88 0 0 1 1.5 0 .88 .88 0 0 1-.5 1.4 .88 .88 0 0 1-1.1-.9h.2a.63 .63 0 0 1 .9-.5 .63 .63 0 0 1 .1 1.1 .63 .63 0 0 1-1-.4v-.2h-.2z" fill-rule="evenodd"/>
<path d="M39.9 118.1a.88 .88 0 0 1 1.5 0 .88 .88 0 0 1-.5 1.4 .88 .88 0 0 1-1.1-.9h.2a.63 .63 0 0 1 .9-.5 .63 .63 0 0 1 .1 1 .63 .63 0 0 1-1-.3v-.2h-.2z" fill-rule="evenodd"/>
<path d="M39.9 123.1a.88 .88 0 0 1 1.5 .1 .88 .88 0 0 1-.5 1.3 .88 .88 0 0 1-1.1-.8h.2a.63 .63 0 0 1 .9-.5 .63 .63 0 0 1 .1 1 .63 .63 0 0 1-1-.3v-.2h-.2z" fill-rule="evenodd"/>
<path d="M39.9 128.2a.88 .88 0 0 1 1.5 .1 .88 .88 0 0 1-.5 1.3 .88 .88 0 0 1-1.1-.8h.2a.63 .63 0 0 1 .9-.6 .63 .63 0 0 1 .1 1.1 .63 .63 0 0 1-1-.3v-.2h-.2z" fill-rule="evenodd"/>
<path d="M39.9 133.3a.88 .88 0 0 1 1.5 0 .88 .88 0 0 1-.5 1.4 .88 .88 0 0 1-1.1-.9h.2a.63 .63 0 0 1 .9-.5 .63 .63 0 0 1 .1 1.1 .63 .63 0 0 1-1-.4v-.2h-.2z" fill-rule="evenodd"/>
<path d="M39.9 138.4a.88 .88 0 0 1 1.5 0 .88 .88 0 0 1-.5 1.4 .88 .88 0 0 1-1.1-.9h.2a.63 .63 0 0 1 .9-.5 .63 .63 0 0 1 .1 1.1 .63 .63 0 0 1-1-.4v-.2h-.2z" fill-rule="evenodd"/>
<path d="M39.9 143.4a.88 .88 0 0 1 1.5 .1 .88 .88 0 0 1-.5 1.3 .88 .88 0 0 1-1.1-.8h.2a.63 .63 0 0 1 .9-.5 .63 .63 0 0 1 .1 1 .63 .63 0 0 1-1-.3v-.2h-.2z" fill-rule="evenodd"/>
<path d="M39.9 148.5a.88 .88 0 0 1 1.5 .1 .88 .88 0 0 1-.5 1.3 .88 .88 0 0 1-1.1-.8h.2a.63 .63 0 0 1 .9-.5 .63 .63 0 0 1 .1 1 .63 .63 0 0 1-1-.3v-.2h-.2z" fill-rule="evenodd"/>
<path d="M39.9 153.6a.88 .88 0 0 1 1.5 .1 .88 .88 0 0 1-.5 1.3 .88 .88 0 0 1-1.1-.8h.2a.63 .63 0 0 1 .9-.6 .63 .63 0 0 1 .1 1.1 .63 .63 0 0 1-1-.3v-.2h-.2z" fill-rule="evenodd"/>
<path d="M39.9 158.7a.88 .88 0 0 1 1.5 0 .88 .88 0 0 1-.5 1.4 .88 .88 0 0 1-1.1-.9h.2a.63 .63 0 0 1 .9-.5 .63 .63 0 0 1 .1 1.1 .63 .63 0 0 1-1-.4v-.2h-.2z" fill-rule="evenodd"/>
<path d="M39.9 163.8a.88 .88 0 0 1 1.5 0 .88 .88 0 0 1-.5 1.4 .88 .88 0 0 1-1.1-.9h.2a.63 .63 0 0 1 .9-.5 .63 .63 0 0 1 .1 1.1 .63 .63 0 0 1-1-.4v-.2h-.2z" fill-rule="evenodd"/>
<path d="M39.9 168.8a.88 .88 0 0 1 1.5 .1 .88 .88 0 0 1-.5 1.3 .88 .88 0 0 1-1.1-.8h.2a.63 .63 0 0 1 .9-.5 .63 .63 0 0 1 .1 1 .63 .63 0 0 1-1-.3v-.2h-.2z" fill-rule="evenodd"/>
<path d="M39.9 173.9a.88 .88 0 0 1 1.5 .1 .88 .88 0 0 1-.5 1.3 .88 .88 0 0 1-1.1-.8h.2a.63 .63 0 0 1 .9-.5 .63 .63 0 0 1 .1 1 .63 .63 0 0 1-1-.3v-.2h-.2z" fill-rule="evenodd"/>
<path d="M39.9 179a.88 .88 0 0 1 1.5 .1 .88 .88 0 0 1-.5 1.3 .88 .88 0 0 1-1.1-.8h.2a.63 .63 0 0 1 .9-.6 .63 .63 0 0 1 .1 1.1 .63 .63 0 0 1-1-.3v-.2h-.2z" fill-rule="evenodd"/>
<path d="M39.9 184.1a.88 .88 0 0 1 1.5 0 .88 .88 0 0 1-.5 1.4 .88 .88 0 0 1-1.1-.9h.2a.63 .63 0 0 1 .9-.5 .63 .63 0 0 1 .1 1.1 .63 .63 0 0 1-1-.4v-.2h-.2z" fill-rule="evenodd"/>
<path d="M39.9 189.2a.88 .88 0 0 1 1.5 0 .88 .88 0 0 1-.5 1.4 .88 .88 0 0 1-1.1-.9h.2a.63 .63 0 0 1 .9-.5 .63 .63 0 0 1 .1 1 .63 .63 0 0 1-1-.3v-.2h-.2z" fill-rule="evenodd"/>
<path d="M39.9 194.2a.88 .88 0 0 1 1.5 .1 .88 .88 0 0 1-.5 1.3 .88 .88 0 0 1-1.1-.8h.2a.63 .63 0 0 1 .9-.5 .63 .63 0 0 1 .1 1 .63 .63 0 0 1-1-.3v-.2h-.2z" fill-rule="evenodd"/>
<path d="M39.9 199.3a.88 .88 0 0 1 1.5 .1 .88 .88 0 0 1-.5 1.3 .88 .88 0 0 1-1.1-.8h.2a.63 .63 0 0 1 .9-.6 .63 .63 0 0 1 .1 1.1 .63 .63 0 0 1-1-.3v-.2h-.2z" fill-rule="evenodd"/>
<path d="M39.9 204.4a.88 .88 0 0 1 1.5 .1 .88 .88 0 0 1-.5 1.3 .88 .88 0 0 1-1.1-.8h.2a.63 .63 0 0 1 .9-.6 .63 .63 0 0 1 .1 1.1 .63 .63 0 0 1-1-.4v-.1h-.2z" fill-rule="evenodd"/>
<path d="M39.9 209.5a.88 .88 0 0 1 1.5 0 .88 .88 0 0 1-.5 1.4 .88 .88 0 0 1-1.1-.9h.2a.63 .63 0 0 1 .9-.5 .63 .63 0 0 1 .1 1.1 .63 .63 0 0 1-1-.4v-.2h-.2z" fill-rule="evenodd"/>
<path d="M39.9 214.6a.88 .88 0 0 1 1.5 0 .88 .88 0 0 1-.5 1.4 .88 .88 0 0 1-1.1-.9h.2a.63 .63 0 0 1 .9-.5 .63 .63 0 0 1 .1 1 .63 .63 0 0 1-1-.3v-.2h-.2z" fill-rule="evenodd"/>
<path d="M39.9 219.6a.88 .88 0 0 1 1.5 .1 .88 .88 0 0 1-.5 1.3 .88 .88 0 0 1-1.1-.8h.2a.63 .63 0 0 1 .9-.5 .63 .63 0 0 1 .1 1 .63 .63 0 0 1-1-.3v-.2h-.2z" fill-rule="evenodd"/>
<path d="M39.9 224.7a.88 .88 0 0 1 1.5 .1 .88 .88 0 0 1-.5 1.3 .88 .88 0 0 1-1.1-.8h.2a.63 .63 0 0 1 .9-.6 .63 .63 0 0 1 .1 1.1 .63 .63 0 0 1-1-.3v-.2h-.2z" fill-rule="evenodd"/>
<path d="M39.9 229.8a.88 .88 0 0 1 1.5 .1 .88 .88 0 0 1-.5 1.3 .88 .88 0 0 1-1.1-.9h.2a.63 .63 0 0 1 .9-.5 .63 .63 0 0 1 .1 1.1 .63 .63 0 0 1-1-.4v-.2h-.2z" fill-rule="evenodd"/>
<path d="M39.9 234.9a.88 .88 0 0 1 1.5 0 .88 .88 0 0 1-.5 1.4 .88 .88 0 0 1-1.1-.9h.2a.63 .63 0 0 1 .9-.5 .63 .63 0 0 1 .1 1.1 .63 .63 0 0 1-1-.4v-.2h-.2z" fill-rule="evenodd"/>
<path d="M95.8 36.8a.89 .89 0 0 1 1.4 0 .89 .89 0 0 1-.4 1.3 .89 .89 0 0 1-1.2-.8h.3a.63 .63 0 0 1 .9-.5 .63 .63 0 0 1 .1 1.1 .63 .63 0 0 1-1-.4v-.2h-.3z" fill-rule="evenodd"/>
<path d="M95.8 41.9a.89 .89 0 0 1 1.4 0 .89 .89 0 0 1-.4 1.3 .89 .89 0 0 1-1.2-.8h.3a.63 .63 0 0 1 .9-.5 .63 .63 0 0 1 .1 1.1 .63 .63 0 0 1-1-.4v-.2h-.3z" fill-rule="evenodd"/>
<path d="M95.8 46.9a.89 .89 0 0 1 1.4 0 .89 .89 0 0 1-.4 1.4 .89 .89 0 0 1-1.2-.8h.3a.63 .63 0 0 1 .9-.5 .63 .63 0 0 1 .1 1 .63 .63 0 0 1-1-.3v-.2h-.3z" fill-rule="evenodd"/>
<path d="M95.8 52a.89 .89 0 0 1 1.4 0 .89 .89 0 0 1-.4 1.4 .89 .89 0 0 1-1.2-.8h.3a.63 .63 0 0 1 .9-.5 .63 .63 0 0 1 .1 1 .63 .63 0 0 1-1-.3v-.2h-.3z" fill-rule="evenodd"/>
<path d="M95.8 57.1a.89 .89 0 0 1 1.4 0 .89 .89 0 0 1-.4 1.4 .89 .89 0 0 1-1.2-.8h.3a.63 .63 0 0 1 .9-.6 .63 .63 0 0 1 .1 1.1 .63 .63 0 0 1-1-.3v-.2h-.3z" fill-rule="evenodd"/>
<path d="M95.8 62.2a.89 .89 0 0 1 1.4 0 .89 .89 0 0 1-.4 1.3 .89 .89 0 0 1-1.2-.8h.3a.63 .63 0 0 1 .9-.5 .63 .63 0 0 1 .1 1.1 .63 .63 0 0 1-1-.4v-.2h-.3z" fill-rule="evenodd"/>
<path d="M95.8 67.3a.89 .89 0 0 1 1.4 0 .89 .89 0 0 1-.4 1.3 .89 .89 0 0 1-1.2-.8h.3a.63 .63 0 0 1 .9-.5 .63 .63 0 0 1 .1 1 .63 .63 0 0 1-1-.3v-.2h-.3z" fill-rule="evenodd"/>
<path d="M95.8 72.3a.89 .89 0 0 1 1.4 0 .89 .89 0 0 1-.4 1.4 .89 .89 0 0 1-1.2-.8h.3a.63 .63 0 0 1 .9-.5 .63 .63 0 0 1 .1 1 .63 .63 0 0 1-1-.3v-.2h-.3z" fill-rule="evenodd"/>
<path d="M95.8 77.4a.89 .89 0 0 1 1.4 0 .89 .89 0 0 1-.4 1.4 .89 .89 0 0 1-1.2-.8h.3a.63 .63 0 0 1 .9-.6 .63 .63 0 0 1 .1 1.1 .63 .63 0 0 1-1-.3v-.2h-.3z" fill-rule="evenodd"/>
<path d="M95.8 82.5a.89 .89 0 0 1 1.4 0 .89 .89 0 0 1-.4 1.4 .89 .89 0 0 1-1.2-.8h.3a.63 .63 0 0 1 .9-.6 .63 .63 0 0 1 .1 1.1 .63 .63 0 0 1-1-.4v-.1h-.3z" fill-rule="evenodd"/>
<path d="M95.8 87.6a.89 .89 0 0 1 1.4 0 .89 .89 0 0 1-.4 1.3 .89 .89 0 0 1-1.2-.8h.3a.63 .63 0 0 1 .9-.5 .63 .63 0 0 1 .1 1.1 .63 .63 0 0 1-1-.4v-.2h-.3z" fill-rule="evenodd"/>
<path d="M95.8 92.7a.89 .89 0 0 1 1.4 0 .89 .89 0 0 1-.4 1.3 .89 .89 0 0 1-1.2-.8h.3a.63 .63 0 0 1 .9-.5 .63 .63 0 0 1 .1 1 .63 .63 0 0 1-1-.3v-.2h-.3z" fill-rule="evenodd"/>
<path d="M95.8 97.7a.89 .89 0 0 1 1.4 0 .89 .89 0 0 1-.4 1.4 .89 .89 0 0 1-1.2-.8h.3a.63 .63 0 0 1 .9-.5 .63 .63 0 0 1 .1 1 .63 .63 0 0 1-1-.3v-.2h-.3z" fill-rule="evenodd"/>
<path d="M95.8 102.8a.89 .89 0 0 1 1.4 0 .89 .89 0 0 1-.4 1.4 .89 .89 0 0 1-1.2-.8h.3a.63 .63 0 0 1 .9-.6 .63 .63 0 0 1 .1 1.1 .63 .63 0 0 1-1-.3v-.2h-.3z" fill-rule="evenodd"/>
<path d="M95.8 107.9a.89 .89 0 0 1 1.4 0 .89 .89 0 0 1-.4 1.4 .89 .89 0 0 1-1.2-.9h.3a.63 .63 0 0 1 .9-.5 .63 .63 0 0 1 .1 1.1 .63 .63 0 0 1-1-.4v-.2h-.3z" fill-rule="evenodd"/>
<path d="M95.8 113a.89 .89 0 0 1 1.4 0 .89 .89 0 0 1-.4 1.3 .89 .89 0 0 1-1.2-.8h.3a.63 .63 0 0 1 .9-.5 .63 .63 0 0 1 .1 1.1 .63 .63 0 0 1-1-.4v-.2h-.3z" fill-rule="evenodd"/>
<path d="M95.8 118.1a.89 .89 0 0 1 1.4 0 .89 .89 0 0 1-.4 1.3 .89 .89 0 0 1-1.2-.8h.3a.63 .63 0 0 1 .9-.5 .63 .63 0 0 1 .1 1 .63 .63 0 0 1-1-.3v-.2h-.3z" fill-rule="evenodd"/>
<path d="M95.8 123.1a.89 .89 0 0 1 1.4 0 .89 .89 0 0 1-.4 1.4 .89 .89 0 0 1-1.2-.8h.3a.63 .63 0 0 1 .9-.5 .63 .63 0 0 1 .1 1 .63 .63 0 0 1-1-.3v-.2h-.3z" fill-rule="evenodd"/>
<path d="M95.8 128.2a.89 .89 0 0 1 1.4 0 .89 .89 0 0 1-.4 1.4 .89 .89 0 0 1-1.2-.8h.3a.63 .63 0 0 1 .9-.6 .63 .63 0 0 1 .1 1.1 .63 .63 0 0 1-1-.3v-.2h-.3z" fill-rule="evenodd"/>
<path d="M95.8 133.3a.89 .89 0 0 1 1.4 0 .89 .89 0 0 1-.4 1.3 .89 .89 0 0 1-1.2-.8h.3a.63 .63 0 0 1 .9-.5 .63 .63 0 0 1 .1 1.1 .63 .63 0 0 1-1-.4v-.2h-.3z" fill-rule="evenodd"/>
<path d="M95.8 138.4a.89 .89 0 0 1 1.4 0 .89 .89 0 0 1-.4 1.3 .89 .89 0 0 1-1.2-.8h.3a.63 .63 0 0 1 .9-.5 .63 .63 0 0 1 .1 1.1 .63 .63 0 0 1-1-.4v-.2h-.3z" fill-rule="evenodd"/>
<path d="M95.8 143.4a.89 .89 0 0 1 1.4 0 .89 .89 0 0 1-.4 1.4 .89 .89 0 0 1-1.2-.8h.3a.63 .63 0 0 1 .9-.5 .63 .63 0 0 1 .1 1 .63 .63 0 0 1-1-.3v-.2h-.3z" fill-rule="evenodd"/>
<path d="M95.8 148.5a.89 .89 0 0 1 1.4 0 .89 .89 0 0 1-.4 1.4 .89 .89 0 0 1-1.2-.8h.3a.63 .63 0 0 1 .9-.5 .63 .63 0 0 1 .1 1 .63 .63 0 0 1-1-.3v-.2h-.3z" fill-rule="evenodd"/>
<path d="M95.8 153.6a.89 .89 0 0 1 1.4 0 .89 .89 0 0 1-.4 1.4 .89 .89 0 0 1-1.2-.8h.3a.63 .63 0 0 1 .9-.6 .63 .63 0 0 1 .1 1.1 .63 .63 0 0 1-1-.3v-.2h-.3z" fill-rule="evenodd"/>
<path d="M95.8 158.7a.89 .89 0 0 1 1.4 0 .89 .89 0 0 1-.4 1.3 .89 .89 0 0 1-1.2-.8h.3a.63 .63 0 0 1 .9-.5 .63 .63 0 0 1 .1 1.1 .63 .63 0 0 1-1-.4v-.2h-.3z" fill-rule="evenodd"/>
<path d="M95.8 163.8a.89 .89 0 0 1 1.4 0 .89 .89 0 0 1-.4 1.3 .89 .89 0 0 1-1.2-.8h.3a.63 .63 0 0 1 .9-.5 .63 .63 0 0 1 .1 1.1 .63 .63 0 0 1-1-.4v-.2h-.3z" fill-rule="evenodd"/>
<path d="M95.8 168.8a.89 .89 0 0 1 1.4 0 .89 .89 0 0 1-.4 1.4 .89 .89 0 0 1-1.2-.8h.3a.63 .63 0 0 1 .9-.5 .63 .63 0 0 1 .1 1 .63 .63 0 0 1-1-.3v-.2h-.3z" fill-rule="evenodd"/>
<path d="M95.8 173.9a.89 .89 0 0 1 1.4 0 .89 .89 0 0 1-.4 1.4 .89 .89 0 0 1-1.2-.8h.3a.63 .63 0 0 1 .9-.5 .63 .63 0 0 1 .1 1 .63 .63 0 0 1-1-.3v-.2h-.3z" fill-rule="evenodd"/>
<path d="M95.8 179a.89 .89 0 0 1 1.4 0 .89 .89 0 0 1-.4 1.4 .89 .89 0 0 1-1.2-.8h.3a.63 .63 0 0 1 .9-.6 .63 .63 0 0 1 .1 1.1 .63 .63 0 0 1-1-.3v-.2h-.3z" fill-rule="evenodd"/>
<path d="M95.8 184.1a.89 .89 0 0 1 1.4 0 .89 .89 0 0 1-.4 1.3 .89 .89 0 0 1-1.2-.8h.3a.63 .63 0 0 1 .9-.5 .63 .63 0 0 1 .1 1.1 .63 .63 0 0 1-1-.4v-.2h-.3z" fill-rule="evenodd"/>
<path d="M95.8 189.2a.89 .89 0 0 1 1.4 0 .89 .89 0 0 1-.4 1.3 .89 .89 0 0 1-1.2-.8h.3a.63 .63 0 0 1 .9-.5 .63 .63 0 0 1 .1 1 .63 .63 0 0 1-1-.3v-.2h-.3z" fill-rule="evenodd"/>
<path d="M95.8 194.2a.89 .89 0 0 1 1.4 0 .89 .89 0 0 1-.4 1.4 .89 .89 0 0 1-1.2-.8h.3a.63 .63 0 0 1 .9-.5 .63 .63 0 0 1 .1 1 .63 .63 0 0 1-1-.3v-.2h-.3z" fill-rule="evenodd"/>
<path d="M95.8 199.3a.89 .89 0 0 1 1.4 0 .89 .89 0 0 1-.4 1.4 .89 .89 0 0 1-1.2-.8h.3a.63 .63 0 0 1 .9-.6 .63 .63 0 0 1 .1 1.1 .63 .63 0 0 1-1-.3v-.2h-.3z" fill-rule="evenodd"/>
<path d="M95.8 204.4a.89 .89 0 0 1 1.4 0 .89 .89 0 0 1-.4 1.4 .89 .89 0 0 1-1.2-.8h.3a.63 .63 0 0 1 .9-.6 .63 .63 0 0 1 .1 1.1 .63 .63 0 0 1-1-.4v-.1h-.3z" fill-rule="evenodd"/>
<path d="M95.8 209.5a.89 .89 0 0 1 1.4 0 .89 .89 0 0 1-.4 1.3 .89 .89 0 0 1-1.2-.8h.3a.63 .63 0 0 1 .9-.5 .63 .63 0 0 1 .1 1.1 .63 .63 0 0 1-1-.4v-.2h-.3z" fill-rule="evenodd"/>
<path d="M95.8 214.6a.89 .89 0 0 1 1.4 0 .89 .89 0 0 1-.4 1.3 .89 .89 0 0 1-1.2-.8h.3a.63 .63 0 0 1 .9-.5 .63 .63 0 0 1 .1 1 .63 .63 0 0 1-1-.3v-.2h-.3z" fill-rule="evenodd"/>
<path d="M95.8 219.6a.89 .89 0 0 1 1.4 0 .89 .89 0 0 1-.4 1.4 .89 .89 0 0 1-1.2-.8h.3a.63 .63 0 0 1 .9-.5 .63 .63 0 0 1 .1 1 .63 .63 0 0 1-1-.3v-.2h-.3z" fill-rule="evenodd"/>
<path d="M95.8 224.7a.89 .89 0 0 1 1.4 0 .89 .89 0 0 1-.4 1.4 .89 .89 0 0 1-1.2-.8h.3a.63 .63 0 0 1 .9-.6 .63 .63 0 0 1 .1 1.1 .63 .63 0 0 1-1-.3v-.2h-.3z" fill-rule="evenodd"/>
<path d="M95.8 229.8a.89 .89 0 0 1 1.4 0 .89 .89 0 0 1-.4 1.4 .89 .89 0 0 1-1.2-.9h.3a.63 .63 0 0 1 .9-.5 .63 .63 0 0 1 .1 1.1 .63 .63 0 0 1-1-.4v-.2h-.3z" fill-rule="evenodd"/>
<path d="M95.8 234.9a.89 .89 0 0 1 1.4 0 .89 .89 0 0 1-.4 1.3 .89 .89 0 0 1-1.2-.8h.3a.63 .63 0 0 1 .9-.5 .63 .63 0 0 1 .1 1.1 .63 .63 0 0 1-1-.4v-.2h-.3z" fill-rule="evenodd"/>
<path d="M177.1 36.8a.9 .9 0 0 1 1.4 0 .9 .9 0 0 1-.4 1.4 .9 .9 0 0 1-1.2-.9h.2a.64 .64 0 0 1 .9-.6 .64 .64 0 0 1 .2 1.1 .64 .64 0 0 1-1-.3l-.1-.2h-.2z" fill-rule="evenodd"/>
<path d="M177.1 41.9a.9 .9 0 0 1 1.4 0 .9 .9 0 0 1-.4 1.4 .9 .9 0 0 1-1.2-.9h.2a.64 .64 0 0 1 .9-.6 .64 .64 0 0 1 .2 1.1 .64 .64 0 0 1-1-.3l-.1-.2h-.2z" fill-rule="evenodd"/>
<path d="M177.1 46.9a.9 .9 0 0 1 1.4 .1 .9 .9 0 0 1-.4 1.4 .9 .9 0 0 1-1.2-.9h.2a.64 .64 0 0 1 .9-.6 .64 .64 0 0 1 .2 1 .64 .64 0 0 1-1-.2l-.1-.2h-.2z" fill-rule="evenodd"/>
<path d="M177.1 52a.9 .9 0 0 1 1.4 .1 .9 .9 0 0 1-.4 1.3 .9 .9 0 0 1-1.2-.8h.2a.64 .64 0 0 1 .9-.6 .64 .64 0 0 1 .2 1 .64 .64 0 0 1-1-.2l-.1-.2h-.2z" fill-rule="evenodd"/>
<path d="M177.1 57.1a.9 .9 0 0 1 1.4 .1 .9 .9 0 0 1-.4 1.3 .9 .9 0 0 1-1.2-.8h.2a.64 .64 0 0 1 .9-.7 .64 .64 0 0 1 .2 1.1 .64 .64 0 0 1-1-.2l-.1-.2h-.2z" fill-rule="evenodd"/>
<path d="M177.1 62.2a.9 .9 0 0 1 1.4 0 .9 .9 0 0 1-.4 1.4 .9 .9 0 0 1-1.2-.9h.2a.64 .64 0 0 1 .9-.6 .64 .64 0 0 1 .2 1.1 .64 .64 0 0 1-1-.3l-.1-.2h-.2z" fill-rule="evenodd"/>
<path d="M177.1 67.3a.9 .9 0 0 1 1.4 0 .9 .9 0 0 1-.4 1.4 .9 .9 0 0 1-1.2-.9h.2a.64 .64 0 0 1 .9-.6 .64 .64 0 0 1 .2 1 .64 .64 0 0 1-1-.2l-.1-.2h-.2z" fill-rule="evenodd"/>
<path d="M177.1 72.3a.9 .9 0 0 1 1.4 .1 .9 .9 0 0 1-.4 1.4 .9 .9 0 0 1-1.2-.9h.2a.64 .64 0 0 1 .9-.6 .64 .64 0 0 1 .2 1 .64 .64 0 0 1-1-.2l-.1-.2h-.2z" fill-rule="evenodd"/>
<path d="M177.1 77.4a.9 .9 0 0 1 1.4 .1 .9 .9 0 0 1-.4 1.3 .9 .9 0 0 1-1.2-.8h.2a.64 .64 0 0 1 .9-.7 .64 .64 0 0 1 .2 1.1 .64 .64 0 0 1-1-.2l-.1-.2h-.2z" fill-rule="evenodd"/>
<path d="M177.1 82.5a.9 .9 0 0 1 1.4 .1 .9 .9 0 0 1-.4 1.3 .9 .9 0 0 1-1.2-.8h.2a.64 .64 0 0 1 .9-.7 .64 .64 0 0 1 .2 1.1 .64 .64 0 0 1-1-.3l-.1-.1h-.2z" fill-rule="evenodd"/>
<path d="M177.1 87.6a.89 .89 0 0 1 1.4 0 .89 .89 0 0 1-.5 1.4 .89 .89 0 0 1-1.1-.9h.2a.64 .64 0 0 1 .9-.6 .64 .64 0 0 1 .2 1 .64 .64 0 0 1-1-.2l-.1-.2h-.2z" fill-rule="evenodd"/>
<path d="M177.1 92.7a.89 .89 0 0 1 1.4 0 .89 .89 0 0 1-.5 1.4 .89 .89 0 0 1-1.1-.9h.2a.64 .64 0 0 1 .9-.6 .64 .64 0 0 1 .2 1 .64 .64 0 0 1-1-.2l-.1-.2h-.2z" fill-rule="evenodd"/>
<path d="M177.1 97.7a.89 .89 0 0 1 1.4 .1 .89 .89 0 0 1-.5 1.4 .89 .89 0 0 1-1.1-.9h.2a.64 .64 0 0 1 .9-.6 .64 .64 0 0 1 .2 1 .64 .64 0 0 1-1-.2l-.1-.2h-.2z" fill-rule="evenodd"/>
<path d="M177.1 102.8a.89 .89 0 0 1 1.4 .1 .89 .89 0 0 1-.5 1.3 .89 .89 0 0 1-1.1-.8h.2a.64 .64 0 0 1 .9-.7 .64 .64 0 0 1 .2 1.1 .64 .64 0 0 1-1-.2l-.1-.2h-.2z" fill-rule="evenodd"/>
<path d="M177.1 107.9a.89 .89 0 0 1 1.4 .1 .89 .89 0 0 1-.5 1.3 .89 .89 0 0 1-1.1-.9h.2a.64 .64 0 0 1 .9-.6 .64 .64 0 0 1 .2 1.1 .64 .64 0 0 1-1-.3l-.1-.2h-.2z" fill-rule="evenodd"/>
<path d="M177.1 113a.89 .89 0 0 1 1.4 0 .89 .89 0 0 1-.5 1.4 .89 .89 0 0 1-1.1-.9h.2a.64 .64 0 0 1 .9-.6 .64 .64 0 0 1 .2 1.1 .64 .64 0 0 1-1-.3l-.1-.2h-.2z" fill-rule="evenodd"/>
<path d="M177.1 118.1a.89 .89 0 0 1 1.4 0 .89 .89 0 0 1-.5 1.4 .89 .89 0 0 1-1.1-.9h.2a.64 .64 0 0 1 .9-.6 .64 .64 0 0 1 .2 1 .64 .64 0 0 1-1-.2l-.1-.2h-.2z" fill-rule="evenodd"/>
<path d="M177.1 123.1a.9 .9 0 0 1 1.4 .1 .9 .9 0 0 1-.4 1.3 .9 .9 0 0 1-1.2-.8h.2a.64 .64 0 0 1 .9-.6 .64 .64 0 0 1 .2 1 .64 .64 0 0 1-1-.2l-.1-.2h-.2z" fill-rule="evenodd"/>
<path d="M177.1 128.2a.9 .9 0 0 1 1.4 .1 .9 .9 0 0 1-.4 1.3 .9 .9 0 0 1-1.2-.8h.2a.64 .64 0 0 1 .9-.7 .64 .64 0 0 1 .2 1.1 .64 .64 0 0 1-1-.2l-.1-.2h-.2z" fill-rule="evenodd"/>
<path d="M177.1 133.3a.9 .9 0 0 1 1.4 0 .9 .9 0 0 1-.4 1.4 .9 .9 0 0 1-1.2-.9h.2a.64 .64 0 0 1 .9-.6 .64 .64 0 0 1 .2 1.1 .64 .64 0 0 1-1-.3l-.1-.2h-.2z" fill-rule="evenodd"/>
<path d="M177.1 138.4a.9 .9 0 0 1 1.4 0 .9 .9 0 0 1-.4 1.4 .9 .9 0 0 1-1.2-.9h.2a.64 .64 0 0 1 .9-.6 .64 .64 0 0 1 .2 1.1 .64 .64 0 0 1-1-.3l-.1-.2h-.2z" fill-rule="evenodd"/>
<path d="M177.1 143.4a.9 .9 0 0 1 1.4 .1 .9 .9 0 0 1-.4 1.4 .9 .9 0 0 1-1.2-.9h.2a.64 .64 0 0 1 .9-.6 .64 .64 0 0 1 .2 1 .64 .64 0 0 1-1-.2l-.1-.2h-.2z" fill-rule="evenodd"/>
<path d="M177.1 148.5a.9 .9 0 0 1 1.4 .1 .9 .9 0 0 1-.4 1.3 .9 .9 0 0 1-1.2-.8h.2a.64 .64 0 0 1 .9-.6 .64 .64 0 0 1 .2 1 .64 .64 0 0 1-1-.2l-.1-.2h-.2z" fill-rule="evenodd"/>
<path d="M177.1 153.6a.9 .9 0 0 1 1.4 .1 .9 .9 0 0 1-.4 1.3 .9 .9 0 0 1-1.2-.8h.2a.64 .64 0 0 1 .9-.7 .64 .64 0 0 1 .2 1.1 .64 .64 0 0 1-1-.2l-.1-.2h-.2z" fill-rule="evenodd"/>
<path d="M177.1 158.7a.9 .9 0 0 1 1.4 0 .9 .9 0 0 1-.4 1.4 .9 .9 0 0 1-1.2-.9h.2a.64 .64 0 0 1 .9-.6 .64 .64 0 0 1 .2 1.1 .64 .64 0 0 1-1-.3l-.1-.2h-.2z" fill-rule="evenodd"/>
<path d="M177.1 163.8a.9 .9 0 0 1 1.4 0 .9 .9 0 0 1-.4 1.4 .9 .9 0 0 1-1.2-.9h.2a.64 .64 0 0 1 .9-.6 .64 .64 0 0 1 .2 1.1 .64 .64 0 0 1-1-.3l-.1-.2h-.2z" fill-rule="evenodd"/>
<path d="M177.1 168.8a.9 .9 0 0 1 1.4 .1 .9 .9 0 0 1-.4 1.4 .9 .9 0 0 1-1.2-.9h.2a.64 .64 0 0 1 .9-.6 .64 .64 0 0 1 .2 1 .64 .64 0 0 1-1-.2l-.1-.2h-.2z" fill-rule="evenodd"/>
<path d="M177.1 173.9a.9 .9 0 0 1 1.4 .1 .9 .9 0 0 1-.4 1.3 .9 .9 0 0 1-1.2-.8h.2a.64 .64 0 0 1 .9-.6 .64 .64 0 0 1 .2 1 .64 .64 0 0 1-1-.2l-.1-.2h-.2z" fill-rule="evenodd"/>
<path d="M177.1 179a.9 .9 0 0 1 1.4 .1 .9 .9 0 0 1-.4 1.3 .9 .9 0 0 1-1.2-.8h.2a.64 .64 0 0 1 .9-.7 .64 .64 0 0 1 .2 1.1 .64 .64 0 0 1-1-.2l-.1-.2h-.2z" fill-rule="evenodd"/>
<path d="M177.1 184.1a.9 .9 0 0 1 1.4 0 .9 .9 0 0 1-.4 1.4 .9 .9 0 0 1-1.2-.9h.2a.64 .64 0 0 1 .9-.6 .64 .64 0 0 1 .2 1.1 .64 .64 0 0 1-1-.3l-.1-.2h-.2z" fill-rule="evenodd"/>
<path d="M177.1 189.2a.9 .9 0 0 1 1.4 0 .9 .9 0 0 1-.4 1.4 .9 .9 0 0 1-1.2-.9h.2a.64 .64 0 0 1 .9-.6 .64 .64 0 0 1 .2 1 .64 .64 0 0 1-1-.2l-.1-.2h-.2z" fill-rule="evenodd"/>
<path d="M177.1 194.2a.9 .9 0 0 1 1.4 .1 .9 .9 0 0 1-.4 1.4 .9 .9 0 0 1-1.2-.9h.2a.64 .64 0 0 1 .9-.6 .64 .64 0 0 1 .2 1 .64 .64 0 0 1-1-.2l-.1-.2h-.2z" fill-rule="evenodd"/>
<path d="M177.1 199.3a.9 .9 0 0 1 1.4 .1 .9 .9 0 0 1-.4 1.3 .9 .9 0 0 1-1.2-.8h.2a.64 .64 0 0 1 .9-.7 .64 .64 0 0 1 .2 1.1 .64 .64 0 0 1-1-.2l-.1-.2h-.2z" fill-rule="evenodd"/>
<path d="M177.1 204.4a.9 .9 0 0 1 1.4 .1 .9 .9 0 0 1-.4 1.3 .9 .9 0 0 1-1.2-.8h.2a.64 .64 0 0 1 .9-.7 .64 .64 0 0 1 .2 1.1 .64 .64 0 0 1-1-.3l-.1-.1h-.2z" fill-rule="evenodd"/>
<path d="M177.1 209.5a.89 .89 0 0 1 1.4 0 .89 .89 0 0 1-.5 1.4 .89 .89 0 0 1-1.1-.9h.2a.64 .64 0 0 1 .9-.6 .64 .64 0 0 1 .2 1 .64 .64 0 0 1-1-.2l-.1-.2h-.2z" fill-rule="evenodd"/>
<path d="M177.1 214.6a.89 .89 0 0 1 1.4 0 .89 .89 0 0 1-.5 1.4 .89 .89 0 0 1-1.1-.9h.2a.64 .64 0 0 1 .9-.6 .64 .64 0 0 1 .2 1 .64 .64 0 0 1-1-.2l-.1-.2h-.2z" fill-rule="evenodd"/>
<path d="M177.1 219.6a.89 .89 0 0 1 1.4 .1 .89 .89 0 0 1-.5 1.4 .89 .89 0 0 1-1.1-.9h.2a.64 .64 0 0 1 .9-.6 .64 .64 0 0 1 .2 1 .64 .64 0 0 1-1-.2l-.1-.2h-.2z" fill-rule="evenodd"/>
<path d="M177.1 224.7a.89 .89 0 0 1 1.4 .1 .89 .89 0 0 1-.5 1.3 .89 .89 0 0 1-1.1-.8h.2a.64 .64 0 0 1 .9-.7 .64 .64 0 0 1 .2 1.1 .64 .64 0 0 1-1-.2l-.1-.2h-.2z" fill-rule="evenodd"/>
<path d="M177.1 229.8a.89 .89 0 0 1 1.4 .1 .89 .89 0 0 1-.5 1.3 .89 .89 0 0 1-1.1-.9h.2a.64 .64 0 0 1 .9-.6 .64 .64 0 0 1 .2 1.1 .64 .64 0 0 1-1-.3l-.1-.2h-.2z" fill-rule="evenodd"/>
<path d="M177.1 234.9a.89 .89 0 0 1 1.4 0 .89 .89 0 0 1-.5 1.4 .89 .89 0 0 1-1.1-.9h.2a.64 .64 0 0 1 .9-.6 .64 .64 0 0 1 .2 1.1 .64 .64 0 0 1-1-.3l-.1-.2h-.2z" fill-rule="evenodd"/>
<path d="M222.8 36.8a.88 .88 0 0 1 1.4 0 .88 .88 0 0 1-.4 1.4 .88 .88 0 0 1-1.2-.9h.3a.63 .63 0 0 1 .9-.5 .63 .63 0 0 1 .1 1.1 .63 .63 0 0 1-1-.4v-.2h-.3z" fill-rule="evenodd"/>
<path d="M222.8 41.9a.88 .88 0 0 1 1.4 0 .88 .88 0 0 1-.4 1.4 .88 .88 0 0 1-1.2-.9h.3a.63 .63 0 0 1 .9-.5 .63 .63 0 0 1 .1 1.1 .63 .63 0 0 1-1-.4v-.2h-.3z" fill-rule="evenodd"/>
<path d="M222.8 46.9a.88 .88 0 0 1 1.4 .1 .88 .88 0 0 1-.4 1.3 .88 .88 0 0 1-1.2-.8h.3a.63 .63 0 0 1 .9-.5 .63 .63 0 0 1 .1 1 .63 .63 0 0 1-1-.3v-.2h-.3z" fill-rule="evenodd"/>
<path d="M222.8 52a.88 .88 0 0 1 1.4 .1 .88 .88 0 0 1-.4 1.3 .88 .88 0 0 1-1.2-.8h.3a.63 .63 0 0 1 .9-.5 .63 .63 0 0 1 .1 1 .63 .63 0 0 1-1-.3v-.2h-.3z" fill-rule="evenodd"/>
<path d="M222.8 57.1a.88 .88 0 0 1 1.4 .1 .88 .88 0 0 1-.4 1.3 .88 .88 0 0 1-1.2-.8h.3a.63 .63 0 0 1 .9-.6 .63 .63 0 0 1 .1 1.1 .63 .63 0 0 1-1-.3v-.2h-.3z" fill-rule="evenodd"/>
<path d="M222.8 62.2a.88 .88 0 0 1 1.4 0 .88 .88 0 0 1-.4 1.4 .88 .88 0 0 1-1.2-.9h.3a.63 .63 0 0 1 .9-.5 .63 .63 0 0 1 .1 1.1 .63 .63 0 0 1-1-.4v-.2h-.3z" fill-rule="evenodd"/>
<path d="M222.8 67.3a.88 .88 0 0 1 1.4 0 .88 .88 0 0 1-.4 1.4 .88 .88 0 0 1-1.2-.9h.3a.63 .63 0 0 1 .9-.5 .63 .63 0 0 1 .1 1 .63 .63 0 0 1-1-.3v-.2h-.3z" fill-rule="evenodd"/>
<path d="M222.8 72.3a.88 .88 0 0 1 1.4 .1 .88 .88 0 0 1-.4 1.3 .88 .88 0 0 1-1.2-.8h.3a.63 .63 0 0 1 .9-.5 .63 .63 0 0 1 .1 1 .63 .63 0 0 1-1-.3v-.2h-.3z" fill-rule="evenodd"/>
<path d="M222.8 77.4a.88 .88 0 0 1 1.4 .1 .88 .88 0 0 1-.4 1.3 .88 .88 0 0 1-1.2-.8h.3a.63 .63 0 0 1 .9-.6 .63 .63 0 0 1 .1 1.1 .63 .63 0 0 1-1-.3v-.2h-.3z" fill-rule="evenodd"/>
<path d="M222.8 82.5a.88 .88 0 0 1 1.4 .1 .88 .88 0 0 1-.4 1.3 .88 .88 0 0 1-1.2-.8h.3a.63 .63 0 0 1 .9-.6 .63 .63 0 0 1 .1 1.1 .63 .63 0 0 1-1-.4v-.1h-.3z" fill-rule="evenodd"/>
<path d="M222.8 87.6a.88 .88 0 0 1 1.4 0 .88 .88 0 0 1-.4 1.4 .88 .88 0 0 1-1.2-.9h.3a.63 .63 0 0 1 .9-.5 .63 .63 0 0 1 .1 1.1 .63 .63 0 0 1-1-.4v-.2h-.3z" fill-rule="evenodd"/>
<path d="M222.8 92.7a.88 .88 0 0 1 1.4 0 .88 .88 0 0 1-.4 1.4 .88 .88 0 0 1-1.2-.9h.3a.63 .63 0 0 1 .9-.5 .63 .63 0 0 1 .1 1 .63 .63 0 0 1-1-.3v-.2h-.3z" fill-rule="evenodd"/>
<path d="M222.8 97.7a.88 .88 0 0 1 1.4 .1 .88 .88 0 0 1-.5 1.3 .88 .88 0 0 1-1.1-.8h.3a.63 .63 0 0 1 .9-.5 .63 .63 0 0 1 .1 1 .63 .63 0 0 1-1-.3v-.2h-.3z" fill-rule="evenodd"/>
<path d="M222.8 102.8a.88 .88 0 0 1 1.4 .1 .88 .88 0 0 1-.5 1.3 .88 .88 0 0 1-1.1-.8h.3a.63 .63 0 0 1 .9-.6 .63 .63 0 0 1 .1 1.1 .63 .63 0 0 1-1-.3v-.2h-.3z" fill-rule="evenodd"/>
<path d="M222.8 107.9a.88 .88 0 0 1 1.4 .1 .88 .88 0 0 1-.5 1.3 .88 .88 0 0 1-1.1-.9h.3a.63 .63 0 0 1 .9-.5 .63 .63 0 0 1 .1 1.1 .63 .63 0 0 1-1-.4v-.2h-.3z" fill-rule="evenodd"/>
<path d="M222.8 113a.88 .88 0 0 1 1.4 0 .88 .88 0 0 1-.5 1.4 .88 .88 0 0 1-1.1-.9h.3a.63 .63 0 0 1 .9-.5 .63 .63 0 0 1 .1 1.1 .63 .63 0 0 1-1-.4v-.2h-.3z" fill-rule="evenodd"/>
<path d="M222.8 118.1a.88 .88 0 0 1 1.4 0 .88 .88 0 0 1-.5 1.4 .88 .88 0 0 1-1.1-.9h.3a.63 .63 0 0 1 .9-.5 .63 .63 0 0 1 .1 1 .63 .63 0 0 1-1-.3v-.2h-.3z" fill-rule="evenodd"/>
<path d="M222.8 123.1a.88 .88 0 0 1 1.4 .1 .88 .88 0 0 1-.4 1.3 .88 .88 0 0 1-1.2-.8h.3a.63 .63 0 0 1 .9-.5 .63 .63 0 0 1 .1 1 .63 .63 0 0 1-1-.3v-.2h-.3z" fill-rule="evenodd"/>
<path d="M222.8 128.2a.88 .88 0 0 1 1.4 .1 .88 .88 0 0 1-.4 1.3 .88 .88 0 0 1-1.2-.8h.3a.63 .63 0 0 1 .9-.6 .63 .63 0 0 1 .1 1.1 .63 .63 0 0 1-1-.3v-.2h-.3z" fill-rule="evenodd"/>
<path d="M222.8 133.3a.88 .88 0 0 1 1.4 0 .88 .88 0 0 1-.4 1.4 .88 .88 0 0 1-1.2-.9h.3a.63 .63 0 0 1 .9-.5 .63 .63 0 0 1 .1 1.1 .63 .63 0 0 1-1-.4v-.2h-.3z" fill-rule="evenodd"/>
<path d="M222.8 138.4a.88 .88 0 0 1 1.4 0 .88 .88 0 0 1-.4 1.4 .88 .88 0 0 1-1.2-.9h.3a.63 .63 0 0 1 .9-.5 .63 .63 0 0 1 .1 1.1 .63 .63 0 0 1-1-.4v-.2h-.3z" fill-rule="evenodd"/>
<path d="M222.8 143.4a.88 .88 0 0 1 1.4 .1 .88 .88 0 0 1-.4 1.3 .88 .88 0 0 1-1.2-.8h.3a.63 .63 0 0 1 .9-.5 .63 .63 0 0 1 .1 1 .63 .63 0 0 1-1-.3v-.2h-.3z" fill-rule="evenodd"/>
<path d="M222.8 148.5a.88 .88 0 0 1 1.4 .1 .88 .88 0 0 1-.4 1.3 .88 .88 0 0 1-1.2-.8h.3a.63 .63 0 0 1 .9-.5 .63 .63 0 0 1 .1 1 .63 .63 0 0 1-1-.3v-.2h-.3z" fill-rule="evenodd"/>
<path d="M222.8 153.6a.88 .88 0 0 1 1.4 .1 .88 .88 0 0 1-.4 1.3 .88 .88 0 0 1-1.2-.8h.3a.63 .63 0 0 1 .9-.6 .63 .63 0 0 1 .1 1.1 .63 .63 0 0 1-1-.3v-.2h-.3z" fill-rule="evenodd"/>
<path d="M222.8 158.7a.88 .88 0 0 1 1.4 0 .88 .88 0 0 1-.4 1.4 .88 .88 0 0 1-1.2-.9h.3a.63 .63 0 0 1 .9-.5 .63 .63 0 0 1 .1 1.1 .63 .63 0 0 1-1-.4v-.2h-.3z" fill-rule="evenodd"/>
<path d="M222.8 163.8a.88 .88 0 0 1 1.4 0 .88 .88 0 0 1-.4 1.4 .88 .88 0 0 1-1.2-.9h.3a.63 .63 0 0 1 .9-.5 .63 .63 0 0 1 .1 1.1 .63 .63 0 0 1-1-.4v-.2h-.3z" fill-rule="evenodd"/>
<path d="M222.8 168.8a.88 .88 0 0 1 1.4 .1 .88 .88 0 0 1-.4 1.3 .88 .88 0 0 1-1.2-.8h.3a.63 .63 0 0 1 .9-.5 .63 .63 0 0 1 .1 1 .63 .63 0 0 1-1-.3v-.2h-.3z" fill-rule="evenodd"/>
<path d="M222.8 173.9a.88 .88 0 0 1 1.4 .1 .88 .88 0 0 1-.4 1.3 .88 .88 0 0 1-1.2-.8h.3a.63 .63 0 0 1 .9-.5 .63 .63 0 0 1 .1 1 .63 .63 0 0 1-1-.3v-.2h-.3z" fill-rule="evenodd"/>
<path d="M222.8 179a.88 .88 0 0 1 1.4 .1 .88 .88 0 0 1-.4 1.3 .88 .88 0 0 1-1.2-.8h.3a.63 .63 0 0 1 .9-.6 .63 .63 0 0 1 .1 1.1 .63 .63 0 0 1-1-.3v-.2h-.3z" fill-rule="evenodd"/>
<path d="M222.8 184.1a.88 .88 0 0 1 1.4 0 .88 .88 0 0 1-.4 1.4 .88 .88 0 0 1-1.2-.9h.3a.63 .63 0 0 1 .9-.5 .63 .63 0 0 1 .1 1.1 .63 .63 0 0 1-1-.4v-.2h-.3z" fill-rule="evenodd"/>
<path d="M222.8 189.2a.88 .88 0 0 1 1.4 0 .88 .88 0 0 1-.4 1.4 .88 .88 0 0 1-1.2-.9h.3a.63 .63 0 0 1 .9-.5 .63 .63 0 0 1 .1 1 .63 .63 0 0 1-1-.3v-.2h-.3z" fill-rule="evenodd"/>
<path d="M222.8 194.2a.88 .88 0 0 1 1.4 .1 .88 .88 0 0 1-.4 1.3 .88 .88 0 0 1-1.2-.8h.3a.63 .63 0 0 1 .9-.5 .63 .63 0 0 1 .1 1 .63 .63 0 0 1-1-.3v-.2h-.3z" fill-rule="evenodd"/>
<path d="M222.8 199.3a.88 .88 0 0 1 1.4 .1 .88 .88 0 0 1-.4 1.3 .88 .88 0 0 1-1.2-.8h.3a.63 .63 0 0 1 .9-.6 .63 .63 0 0 1 .1 1.1 .63 .63 0 0 1-1-.3v-.2h-.3z" fill-rule="evenodd"/>
<path d="M222.8 204.4a.88 .88 0 0 1 1.4 .1 .88 .88 0 0 1-.4 1.3 .88 .88 0 0 1-1.2-.8h.3a.63 .63 0 0 1 .9-.6 .63 .63 0 0 1 .1 1.1 .63 .63 0 0 1-1-.4v-.1h-.3z" fill-rule="evenodd"/>
<path d="M222.8 209.5a.88 .88 0 0 1 1.4 0 .88 .88 0 0 1-.4 1.4 .88 .88 0 0 1-1.2-.9h.3a.63 .63 0 0 1 .9-.5 .63 .63 0 0 1 .1 1.1 .63 .63 0 0 1-1-.4v-.2h-.3z" fill-rule="evenodd"/>
<path d="M222.8 214.6a.88 .88 0 0 1 1.4 0 .88 .88 0 0 1-.4 1.4 .88 .88 0 0 1-1.2-.9h.3a.63 .63 0 0 1 .9-.5 .63 .63 0 0 1 .1 1 .63 .63 0 0 1-1-.3v-.2h-.3z" fill-rule="evenodd"/>
<path d="M222.8 219.6a.88 .88 0 0 1 1.4 .1 .88 .88 0 0 1-.5 1.3 .88 .88 0 0 1-1.1-.8h.3a.63 .63 0 0 1 .9-.5 .63 .63 0 0 1 .1 1 .63 .63 0 0 1-1-.3v-.2h-.3z" fill-rule="evenodd"/>
<path d="M222.8 224.7a.88 .88 0 0 1 1.4 .1 .88 .88 0 0 1-.5 1.3 .88 .88 0 0 1-1.1-.8h.3a.63 .63 0 0 1 .9-.6 .63 .63 0 0 1 .1 1.1 .63 .63 0 0 1-1-.3v-.2h-.3z" fill-rule="evenodd"/>
<path d="M222.8 229.8a.88 .88 0 0 1 1.4 .1 .88 .88 0 0 1-.5 1.3 .88 .88 0 0 1-1.1-.9h.3a.63 .63 0 0 1 .9-.5 .63 .63 0 0 1 .1 1.1 .63 .63 0 0 1-1-.4v-.2h-.3z" fill-rule="evenodd"/>
<path d="M222.8 234.9a.88 .88 0 0 1 1.4 0 .88 .88 0 0 1-.5 1.4 .88 .88 0 0 1-1.1-.9h.3a.63 .63 0 0 1 .9-.5 .63 .63 0 0 1 .1 1.1 .63 .63 0 0 1-1-.4v-.2h-.3z" fill-rule="evenodd"/>
</g>
<path d="M348.8 70.5h7.7v15.2h-7.7zM350.5 128.8h7.6v38.1h-7.6zM350.5 179.6h7.6v38h-7.6z" fill="none" stroke="#c90d0c" stroke-width=".42"/>
<path d="M16.5 15.7h387.3v260.4h-387.3z" fill="none" stroke="#c90d0c" stroke-width=".32"/>
<g fill="none" stroke="#0dab76" stroke-width=".21">
<path d="M232.4 37.3h7.6M186.7 52.6h7.6M186.7 47.5h7.6M186.7 42.4h7.6M232.4 57.7h7.6M232.4 52.6h7.6M232.4 47.5h7.6M232.4 42.4h7.6M186.7 62.7h7.6M232.4 67.8h7.6M232.4 72.9h7.6M232.4 78h7.6"/>
<path d="M232.4 62.7h7.6M323.8 70.4v12.8h28.9M328.9 70.4v10.3h23.8M334 70.4v7.7h18.7M339 70.4v5h13.7v.2M344.1 70.4v2.7h8.6M49.5 88.1h7.6M49.5 93.2h7.6M105.4 88.1h7.6M186.7 83.1h7.6M186.7 88.1h7.6M232.4 83.1h7.6"/>
<path d="M232.4 88.1h7.6M232.4 93.2h7.6M49.5 113.5h7.6M49.5 118.6h7.6M105.4 113.5h7.6M49.5 138.9h7.6M49.5 123.7h7.6M105.4 138.9h7.6M186.7 133.8h7.6M186.7 138.9h7.6M186.7 128.8h7.6M232.4 128.8h7.6"/>
<path d="M295.9 131.3h58.4M295.9 136.4h58.4M306 133.8h48.3M306 138.9h48.3M49.5 154.2h7.6M105.4 154.2h7.6M105.4 144h7.6M105.4 149.1h7.6M186.7 154.2h7.6M186.7 144h7.6M186.7 149.1h7.6M232.4 154.2h7.6"/>
<path d="M295.9 141.5h58.4M326.3 154.2h28M326.3 144h28M326.3 149.1h28M326.3 159.2h28M336.5 146.5h17.8M336.5 151.6h17.8M336.5 156.7h17.8M105.4 169.4h7.6M186.7 179.6h7.6M232.4 179.6h7.6M326.3 164.3h28"/>
<path d="M336.5 161.8h17.8M295.9 182.1h58.4M326.3 184.6h28M326.3 189.7h28M326.3 194.8h28M326.3 199.9h28M336.5 187.2h17.8M336.5 192.3h17.8M336.5 197.3h17.8M105.4 215.1h7.6M326.3 205h28M326.3 210h28"/>
<path d="M326.3 215.1h28M336.5 202.4h17.8M336.5 207.5h17.8M336.5 212.6h17.8M49.5 220.2h5.1M49.5 230.3h5.1M49.5 225.3h5.1M49.5 235.4h5.1"/>
</g>
<use href="#words"/>
</svg>
